VERSION 5.8 ;
BUSBITCHARS "[]" ;
DIVIDERCHAR "/" ;
UNITS
    DATABASE MICRONS 1000 ;
END UNITS

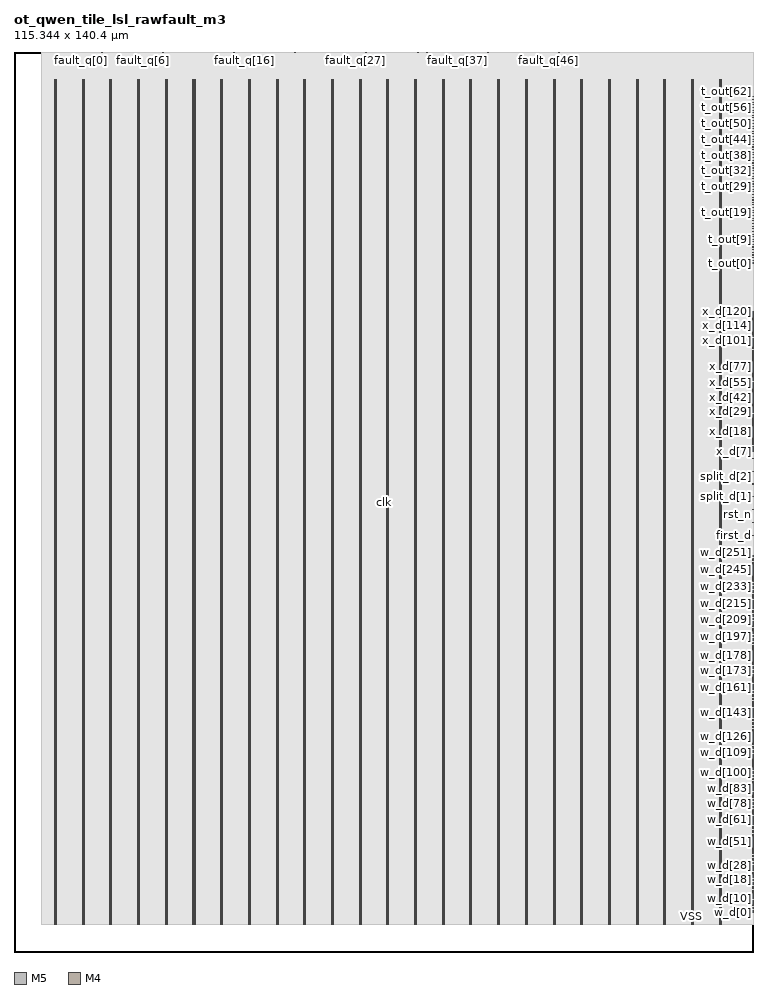
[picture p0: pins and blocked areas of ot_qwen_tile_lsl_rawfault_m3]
MACRO ot_qwen_tile_lsl_rawfault_m3
  FOREIGN ot_qwen_tile_lsl_rawfault_m3 0 0 ;
  CLASS BLOCK ;
  SIZE 115.344 BY 140.4 ;
  PIN clk
    DIRECTION INPUT ;
    USE SIGNAL ;
    PORT
      LAYER M5 ;
        RECT  57.636 69.96 57.684 70.44 ;
    END
  END clk
  PIN fault_q[0]
    DIRECTION OUTPUT ;
    USE SIGNAL ;
    PORT
      LAYER M5 ;
        RECT  10.368 140.316 10.392 140.4 ;
    END
  END fault_q[0]
  PIN fault_q[10]
    DIRECTION OUTPUT ;
    USE SIGNAL ;
    PORT
      LAYER M5 ;
        RECT  26.4 140.316 26.424 140.4 ;
    END
  END fault_q[10]
  PIN fault_q[11]
    DIRECTION OUTPUT ;
    USE SIGNAL ;
    PORT
      LAYER M5 ;
        RECT  27.792 140.316 27.816 140.4 ;
    END
  END fault_q[11]
  PIN fault_q[12]
    DIRECTION OUTPUT ;
    USE SIGNAL ;
    PORT
      LAYER M5 ;
        RECT  29.568 140.316 29.592 140.4 ;
    END
  END fault_q[12]
  PIN fault_q[13]
    DIRECTION OUTPUT ;
    USE SIGNAL ;
    PORT
      LAYER M5 ;
        RECT  31.152 140.316 31.176 140.4 ;
    END
  END fault_q[13]
  PIN fault_q[14]
    DIRECTION OUTPUT ;
    USE SIGNAL ;
    PORT
      LAYER M5 ;
        RECT  32.736 140.316 32.76 140.4 ;
    END
  END fault_q[14]
  PIN fault_q[15]
    DIRECTION OUTPUT ;
    USE SIGNAL ;
    PORT
      LAYER M5 ;
        RECT  34.32 140.316 34.344 140.4 ;
    END
  END fault_q[15]
  PIN fault_q[16]
    DIRECTION OUTPUT ;
    USE SIGNAL ;
    PORT
      LAYER M5 ;
        RECT  35.904 140.316 35.928 140.4 ;
    END
  END fault_q[16]
  PIN fault_q[17]
    DIRECTION OUTPUT ;
    USE SIGNAL ;
    PORT
      LAYER M5 ;
        RECT  37.488 140.316 37.512 140.4 ;
    END
  END fault_q[17]
  PIN fault_q[18]
    DIRECTION OUTPUT ;
    USE SIGNAL ;
    PORT
      LAYER M5 ;
        RECT  39.072 140.316 39.096 140.4 ;
    END
  END fault_q[18]
  PIN fault_q[19]
    DIRECTION OUTPUT ;
    USE SIGNAL ;
    PORT
      LAYER M5 ;
        RECT  40.656 140.316 40.68 140.4 ;
    END
  END fault_q[19]
  PIN fault_q[1]
    DIRECTION OUTPUT ;
    USE SIGNAL ;
    PORT
      LAYER M5 ;
        RECT  12.144 140.316 12.168 140.4 ;
    END
  END fault_q[1]
  PIN fault_q[20]
    DIRECTION OUTPUT ;
    USE SIGNAL ;
    PORT
      LAYER M5 ;
        RECT  42.24 140.316 42.264 140.4 ;
    END
  END fault_q[20]
  PIN fault_q[21]
    DIRECTION OUTPUT ;
    USE SIGNAL ;
    PORT
      LAYER M5 ;
        RECT  43.824 140.316 43.848 140.4 ;
    END
  END fault_q[21]
  PIN fault_q[22]
    DIRECTION OUTPUT ;
    USE SIGNAL ;
    PORT
      LAYER M5 ;
        RECT  45.024 140.316 45.048 140.4 ;
    END
  END fault_q[22]
  PIN fault_q[23]
    DIRECTION OUTPUT ;
    USE SIGNAL ;
    PORT
      LAYER M5 ;
        RECT  46.992 140.316 47.016 140.4 ;
    END
  END fault_q[23]
  PIN fault_q[24]
    DIRECTION OUTPUT ;
    USE SIGNAL ;
    PORT
      LAYER M5 ;
        RECT  48.576 140.316 48.6 140.4 ;
    END
  END fault_q[24]
  PIN fault_q[25]
    DIRECTION OUTPUT ;
    USE SIGNAL ;
    PORT
      LAYER M5 ;
        RECT  50.16 140.316 50.184 140.4 ;
    END
  END fault_q[25]
  PIN fault_q[26]
    DIRECTION OUTPUT ;
    USE SIGNAL ;
    PORT
      LAYER M5 ;
        RECT  51.744 140.316 51.768 140.4 ;
    END
  END fault_q[26]
  PIN fault_q[27]
    DIRECTION OUTPUT ;
    USE SIGNAL ;
    PORT
      LAYER M5 ;
        RECT  53.328 140.316 53.352 140.4 ;
    END
  END fault_q[27]
  PIN fault_q[28]
    DIRECTION OUTPUT ;
    USE SIGNAL ;
    PORT
      LAYER M5 ;
        RECT  54.912 140.316 54.936 140.4 ;
    END
  END fault_q[28]
  PIN fault_q[29]
    DIRECTION OUTPUT ;
    USE SIGNAL ;
    PORT
      LAYER M5 ;
        RECT  56.496 140.316 56.52 140.4 ;
    END
  END fault_q[29]
  PIN fault_q[2]
    DIRECTION OUTPUT ;
    USE SIGNAL ;
    PORT
      LAYER M5 ;
        RECT  13.728 140.316 13.752 140.4 ;
    END
  END fault_q[2]
  PIN fault_q[30]
    DIRECTION OUTPUT ;
    USE SIGNAL ;
    PORT
      LAYER M5 ;
        RECT  57.888 140.316 57.912 140.4 ;
    END
  END fault_q[30]
  PIN fault_q[31]
    DIRECTION OUTPUT ;
    USE SIGNAL ;
    PORT
      LAYER M5 ;
        RECT  59.664 140.316 59.688 140.4 ;
    END
  END fault_q[31]
  PIN fault_q[32]
    DIRECTION OUTPUT ;
    USE SIGNAL ;
    PORT
      LAYER M5 ;
        RECT  61.248 140.316 61.272 140.4 ;
    END
  END fault_q[32]
  PIN fault_q[33]
    DIRECTION OUTPUT ;
    USE SIGNAL ;
    PORT
      LAYER M5 ;
        RECT  63.024 140.316 63.048 140.4 ;
    END
  END fault_q[33]
  PIN fault_q[34]
    DIRECTION OUTPUT ;
    USE SIGNAL ;
    PORT
      LAYER M5 ;
        RECT  64.416 140.316 64.44 140.4 ;
    END
  END fault_q[34]
  PIN fault_q[35]
    DIRECTION OUTPUT ;
    USE SIGNAL ;
    PORT
      LAYER M5 ;
        RECT  66 140.316 66.024 140.4 ;
    END
  END fault_q[35]
  PIN fault_q[36]
    DIRECTION OUTPUT ;
    USE SIGNAL ;
    PORT
      LAYER M5 ;
        RECT  67.584 140.316 67.608 140.4 ;
    END
  END fault_q[36]
  PIN fault_q[37]
    DIRECTION OUTPUT ;
    USE SIGNAL ;
    PORT
      LAYER M5 ;
        RECT  69.168 140.316 69.192 140.4 ;
    END
  END fault_q[37]
  PIN fault_q[38]
    DIRECTION OUTPUT ;
    USE SIGNAL ;
    PORT
      LAYER M5 ;
        RECT  70.752 140.316 70.776 140.4 ;
    END
  END fault_q[38]
  PIN fault_q[39]
    DIRECTION OUTPUT ;
    USE SIGNAL ;
    PORT
      LAYER M5 ;
        RECT  72.336 140.316 72.36 140.4 ;
    END
  END fault_q[39]
  PIN fault_q[3]
    DIRECTION OUTPUT ;
    USE SIGNAL ;
    PORT
      LAYER M5 ;
        RECT  15.504 140.316 15.528 140.4 ;
    END
  END fault_q[3]
  PIN fault_q[40]
    DIRECTION OUTPUT ;
    USE SIGNAL ;
    PORT
      LAYER M5 ;
        RECT  73.92 140.316 73.944 140.4 ;
    END
  END fault_q[40]
  PIN fault_q[41]
    DIRECTION OUTPUT ;
    USE SIGNAL ;
    PORT
      LAYER M5 ;
        RECT  75.312 140.316 75.336 140.4 ;
    END
  END fault_q[41]
  PIN fault_q[42]
    DIRECTION OUTPUT ;
    USE SIGNAL ;
    PORT
      LAYER M5 ;
        RECT  77.088 140.316 77.112 140.4 ;
    END
  END fault_q[42]
  PIN fault_q[43]
    DIRECTION OUTPUT ;
    USE SIGNAL ;
    PORT
      LAYER M5 ;
        RECT  78.672 140.316 78.696 140.4 ;
    END
  END fault_q[43]
  PIN fault_q[44]
    DIRECTION OUTPUT ;
    USE SIGNAL ;
    PORT
      LAYER M5 ;
        RECT  80.256 140.316 80.28 140.4 ;
    END
  END fault_q[44]
  PIN fault_q[45]
    DIRECTION OUTPUT ;
    USE SIGNAL ;
    PORT
      LAYER M5 ;
        RECT  81.84 140.316 81.864 140.4 ;
    END
  END fault_q[45]
  PIN fault_q[46]
    DIRECTION OUTPUT ;
    USE SIGNAL ;
    PORT
      LAYER M5 ;
        RECT  83.424 140.316 83.448 140.4 ;
    END
  END fault_q[46]
  PIN fault_q[47]
    DIRECTION OUTPUT ;
    USE SIGNAL ;
    PORT
      LAYER M5 ;
        RECT  85.008 140.316 85.032 140.4 ;
    END
  END fault_q[47]
  PIN fault_q[48]
    DIRECTION OUTPUT ;
    USE SIGNAL ;
    PORT
      LAYER M5 ;
        RECT  86.592 140.316 86.616 140.4 ;
    END
  END fault_q[48]
  PIN fault_q[49]
    DIRECTION OUTPUT ;
    USE SIGNAL ;
    PORT
      LAYER M5 ;
        RECT  88.176 140.316 88.2 140.4 ;
    END
  END fault_q[49]
  PIN fault_q[4]
    DIRECTION OUTPUT ;
    USE SIGNAL ;
    PORT
      LAYER M5 ;
        RECT  16.896 140.316 16.92 140.4 ;
    END
  END fault_q[4]
  PIN fault_q[5]
    DIRECTION OUTPUT ;
    USE SIGNAL ;
    PORT
      LAYER M5 ;
        RECT  18.48 140.316 18.504 140.4 ;
    END
  END fault_q[5]
  PIN fault_q[6]
    DIRECTION OUTPUT ;
    USE SIGNAL ;
    PORT
      LAYER M5 ;
        RECT  20.064 140.316 20.088 140.4 ;
    END
  END fault_q[6]
  PIN fault_q[7]
    DIRECTION OUTPUT ;
    USE SIGNAL ;
    PORT
      LAYER M5 ;
        RECT  21.648 140.316 21.672 140.4 ;
    END
  END fault_q[7]
  PIN fault_q[8]
    DIRECTION OUTPUT ;
    USE SIGNAL ;
    PORT
      LAYER M5 ;
        RECT  23.232 140.316 23.256 140.4 ;
    END
  END fault_q[8]
  PIN fault_q[9]
    DIRECTION OUTPUT ;
    USE SIGNAL ;
    PORT
      LAYER M5 ;
        RECT  24.816 140.316 24.84 140.4 ;
    END
  END fault_q[9]
  PIN first_d
    DIRECTION INPUT ;
    USE SIGNAL ;
    PORT
      LAYER M4 ;
        RECT  115.26 64.992 115.344 65.016 ;
    END
  END first_d
  PIN rst_n
    DIRECTION INPUT ;
    USE SIGNAL ;
    PORT
      LAYER M4 ;
        RECT  115.26 67.008 115.344 67.032 ;
    END
  END rst_n
  PIN split_d[0]
    DIRECTION INPUT ;
    USE SIGNAL ;
    PORT
      LAYER M4 ;
        RECT  115.26 68.976 115.344 69 ;
    END
  END split_d[0]
  PIN split_d[1]
    DIRECTION INPUT ;
    USE SIGNAL ;
    PORT
      LAYER M4 ;
        RECT  115.26 70.992 115.344 71.016 ;
    END
  END split_d[1]
  PIN split_d[2]
    DIRECTION INPUT ;
    USE SIGNAL ;
    PORT
      LAYER M4 ;
        RECT  115.26 73.008 115.344 73.032 ;
    END
  END split_d[2]
  PIN split_d[3]
    DIRECTION INPUT ;
    USE SIGNAL ;
    PORT
      LAYER M4 ;
        RECT  115.26 74.976 115.344 75 ;
    END
  END split_d[3]
  PIN t_out[0]
    DIRECTION OUTPUT ;
    USE SIGNAL ;
    PORT
      LAYER M4 ;
        RECT  115.26 107.472 115.344 107.496 ;
    END
  END t_out[0]
  PIN t_out[10]
    DIRECTION OUTPUT ;
    USE SIGNAL ;
    PORT
      LAYER M4 ;
        RECT  115.26 111.6 115.344 111.624 ;
    END
  END t_out[10]
  PIN t_out[11]
    DIRECTION OUTPUT ;
    USE SIGNAL ;
    PORT
      LAYER M4 ;
        RECT  115.26 111.984 115.344 112.008 ;
    END
  END t_out[11]
  PIN t_out[12]
    DIRECTION OUTPUT ;
    USE SIGNAL ;
    PORT
      LAYER M4 ;
        RECT  115.26 112.416 115.344 112.44 ;
    END
  END t_out[12]
  PIN t_out[13]
    DIRECTION OUTPUT ;
    USE SIGNAL ;
    PORT
      LAYER M4 ;
        RECT  115.26 112.848 115.344 112.872 ;
    END
  END t_out[13]
  PIN t_out[14]
    DIRECTION OUTPUT ;
    USE SIGNAL ;
    PORT
      LAYER M4 ;
        RECT  115.26 113.232 115.344 113.256 ;
    END
  END t_out[14]
  PIN t_out[15]
    DIRECTION OUTPUT ;
    USE SIGNAL ;
    PORT
      LAYER M4 ;
        RECT  115.26 113.664 115.344 113.688 ;
    END
  END t_out[15]
  PIN t_out[16]
    DIRECTION OUTPUT ;
    USE SIGNAL ;
    PORT
      LAYER M4 ;
        RECT  115.26 114.048 115.344 114.072 ;
    END
  END t_out[16]
  PIN t_out[17]
    DIRECTION OUTPUT ;
    USE SIGNAL ;
    PORT
      LAYER M4 ;
        RECT  115.26 114.48 115.344 114.504 ;
    END
  END t_out[17]
  PIN t_out[18]
    DIRECTION OUTPUT ;
    USE SIGNAL ;
    PORT
      LAYER M4 ;
        RECT  115.26 114.864 115.344 114.888 ;
    END
  END t_out[18]
  PIN t_out[19]
    DIRECTION OUTPUT ;
    USE SIGNAL ;
    PORT
      LAYER M4 ;
        RECT  115.26 115.296 115.344 115.32 ;
    END
  END t_out[19]
  PIN t_out[1]
    DIRECTION OUTPUT ;
    USE SIGNAL ;
    PORT
      LAYER M4 ;
        RECT  115.26 107.904 115.344 107.928 ;
    END
  END t_out[1]
  PIN t_out[20]
    DIRECTION OUTPUT ;
    USE SIGNAL ;
    PORT
      LAYER M4 ;
        RECT  115.26 115.68 115.344 115.704 ;
    END
  END t_out[20]
  PIN t_out[21]
    DIRECTION OUTPUT ;
    USE SIGNAL ;
    PORT
      LAYER M4 ;
        RECT  115.26 116.112 115.344 116.136 ;
    END
  END t_out[21]
  PIN t_out[22]
    DIRECTION OUTPUT ;
    USE SIGNAL ;
    PORT
      LAYER M4 ;
        RECT  115.26 116.544 115.344 116.568 ;
    END
  END t_out[22]
  PIN t_out[23]
    DIRECTION OUTPUT ;
    USE SIGNAL ;
    PORT
      LAYER M4 ;
        RECT  115.26 116.928 115.344 116.952 ;
    END
  END t_out[23]
  PIN t_out[24]
    DIRECTION OUTPUT ;
    USE SIGNAL ;
    PORT
      LAYER M4 ;
        RECT  115.26 117.312 115.344 117.336 ;
    END
  END t_out[24]
  PIN t_out[25]
    DIRECTION OUTPUT ;
    USE SIGNAL ;
    PORT
      LAYER M4 ;
        RECT  115.26 117.744 115.344 117.768 ;
    END
  END t_out[25]
  PIN t_out[26]
    DIRECTION OUTPUT ;
    USE SIGNAL ;
    PORT
      LAYER M4 ;
        RECT  115.26 118.128 115.344 118.152 ;
    END
  END t_out[26]
  PIN t_out[27]
    DIRECTION OUTPUT ;
    USE SIGNAL ;
    PORT
      LAYER M4 ;
        RECT  115.26 118.608 115.344 118.632 ;
    END
  END t_out[27]
  PIN t_out[28]
    DIRECTION OUTPUT ;
    USE SIGNAL ;
    PORT
      LAYER M4 ;
        RECT  115.26 118.992 115.344 119.016 ;
    END
  END t_out[28]
  PIN t_out[29]
    DIRECTION OUTPUT ;
    USE SIGNAL ;
    PORT
      LAYER M4 ;
        RECT  115.26 119.424 115.344 119.448 ;
    END
  END t_out[29]
  PIN t_out[2]
    DIRECTION OUTPUT ;
    USE SIGNAL ;
    PORT
      LAYER M4 ;
        RECT  115.26 108.288 115.344 108.312 ;
    END
  END t_out[2]
  PIN t_out[30]
    DIRECTION OUTPUT ;
    USE SIGNAL ;
    PORT
      LAYER M4 ;
        RECT  115.26 119.808 115.344 119.832 ;
    END
  END t_out[30]
  PIN t_out[31]
    DIRECTION OUTPUT ;
    USE SIGNAL ;
    PORT
      LAYER M4 ;
        RECT  115.26 120.192 115.344 120.216 ;
    END
  END t_out[31]
  PIN t_out[32]
    DIRECTION OUTPUT ;
    USE SIGNAL ;
    PORT
      LAYER M4 ;
        RECT  115.26 120.624 115.344 120.648 ;
    END
  END t_out[32]
  PIN t_out[33]
    DIRECTION OUTPUT ;
    USE SIGNAL ;
    PORT
      LAYER M4 ;
        RECT  115.26 121.008 115.344 121.032 ;
    END
  END t_out[33]
  PIN t_out[34]
    DIRECTION OUTPUT ;
    USE SIGNAL ;
    PORT
      LAYER M4 ;
        RECT  115.26 121.488 115.344 121.512 ;
    END
  END t_out[34]
  PIN t_out[35]
    DIRECTION OUTPUT ;
    USE SIGNAL ;
    PORT
      LAYER M4 ;
        RECT  115.26 121.872 115.344 121.896 ;
    END
  END t_out[35]
  PIN t_out[36]
    DIRECTION OUTPUT ;
    USE SIGNAL ;
    PORT
      LAYER M4 ;
        RECT  115.26 122.304 115.344 122.328 ;
    END
  END t_out[36]
  PIN t_out[37]
    DIRECTION OUTPUT ;
    USE SIGNAL ;
    PORT
      LAYER M4 ;
        RECT  115.26 122.688 115.344 122.712 ;
    END
  END t_out[37]
  PIN t_out[38]
    DIRECTION OUTPUT ;
    USE SIGNAL ;
    PORT
      LAYER M4 ;
        RECT  115.26 123.072 115.344 123.096 ;
    END
  END t_out[38]
  PIN t_out[39]
    DIRECTION OUTPUT ;
    USE SIGNAL ;
    PORT
      LAYER M4 ;
        RECT  115.26 123.504 115.344 123.528 ;
    END
  END t_out[39]
  PIN t_out[3]
    DIRECTION OUTPUT ;
    USE SIGNAL ;
    PORT
      LAYER M4 ;
        RECT  115.26 108.72 115.344 108.744 ;
    END
  END t_out[3]
  PIN t_out[40]
    DIRECTION OUTPUT ;
    USE SIGNAL ;
    PORT
      LAYER M4 ;
        RECT  115.26 123.888 115.344 123.912 ;
    END
  END t_out[40]
  PIN t_out[41]
    DIRECTION OUTPUT ;
    USE SIGNAL ;
    PORT
      LAYER M4 ;
        RECT  115.26 124.368 115.344 124.392 ;
    END
  END t_out[41]
  PIN t_out[42]
    DIRECTION OUTPUT ;
    USE SIGNAL ;
    PORT
      LAYER M4 ;
        RECT  115.26 124.752 115.344 124.776 ;
    END
  END t_out[42]
  PIN t_out[43]
    DIRECTION OUTPUT ;
    USE SIGNAL ;
    PORT
      LAYER M4 ;
        RECT  115.26 125.136 115.344 125.16 ;
    END
  END t_out[43]
  PIN t_out[44]
    DIRECTION OUTPUT ;
    USE SIGNAL ;
    PORT
      LAYER M4 ;
        RECT  115.26 125.568 115.344 125.592 ;
    END
  END t_out[44]
  PIN t_out[45]
    DIRECTION OUTPUT ;
    USE SIGNAL ;
    PORT
      LAYER M4 ;
        RECT  115.26 125.952 115.344 125.976 ;
    END
  END t_out[45]
  PIN t_out[46]
    DIRECTION OUTPUT ;
    USE SIGNAL ;
    PORT
      LAYER M4 ;
        RECT  115.26 126.384 115.344 126.408 ;
    END
  END t_out[46]
  PIN t_out[47]
    DIRECTION OUTPUT ;
    USE SIGNAL ;
    PORT
      LAYER M4 ;
        RECT  115.26 126.768 115.344 126.792 ;
    END
  END t_out[47]
  PIN t_out[48]
    DIRECTION OUTPUT ;
    USE SIGNAL ;
    PORT
      LAYER M4 ;
        RECT  115.26 127.248 115.344 127.272 ;
    END
  END t_out[48]
  PIN t_out[49]
    DIRECTION OUTPUT ;
    USE SIGNAL ;
    PORT
      LAYER M4 ;
        RECT  115.26 127.632 115.344 127.656 ;
    END
  END t_out[49]
  PIN t_out[4]
    DIRECTION OUTPUT ;
    USE SIGNAL ;
    PORT
      LAYER M4 ;
        RECT  115.26 109.104 115.344 109.128 ;
    END
  END t_out[4]
  PIN t_out[50]
    DIRECTION OUTPUT ;
    USE SIGNAL ;
    PORT
      LAYER M4 ;
        RECT  115.26 128.016 115.344 128.04 ;
    END
  END t_out[50]
  PIN t_out[51]
    DIRECTION OUTPUT ;
    USE SIGNAL ;
    PORT
      LAYER M4 ;
        RECT  115.26 128.448 115.344 128.472 ;
    END
  END t_out[51]
  PIN t_out[52]
    DIRECTION OUTPUT ;
    USE SIGNAL ;
    PORT
      LAYER M4 ;
        RECT  115.26 128.832 115.344 128.856 ;
    END
  END t_out[52]
  PIN t_out[53]
    DIRECTION OUTPUT ;
    USE SIGNAL ;
    PORT
      LAYER M4 ;
        RECT  115.26 129.264 115.344 129.288 ;
    END
  END t_out[53]
  PIN t_out[54]
    DIRECTION OUTPUT ;
    USE SIGNAL ;
    PORT
      LAYER M4 ;
        RECT  115.26 129.648 115.344 129.672 ;
    END
  END t_out[54]
  PIN t_out[55]
    DIRECTION OUTPUT ;
    USE SIGNAL ;
    PORT
      LAYER M4 ;
        RECT  115.26 130.128 115.344 130.152 ;
    END
  END t_out[55]
  PIN t_out[56]
    DIRECTION OUTPUT ;
    USE SIGNAL ;
    PORT
      LAYER M4 ;
        RECT  115.26 130.512 115.344 130.536 ;
    END
  END t_out[56]
  PIN t_out[57]
    DIRECTION OUTPUT ;
    USE SIGNAL ;
    PORT
      LAYER M4 ;
        RECT  115.26 130.896 115.344 130.92 ;
    END
  END t_out[57]
  PIN t_out[58]
    DIRECTION OUTPUT ;
    USE SIGNAL ;
    PORT
      LAYER M4 ;
        RECT  115.26 131.328 115.344 131.352 ;
    END
  END t_out[58]
  PIN t_out[59]
    DIRECTION OUTPUT ;
    USE SIGNAL ;
    PORT
      LAYER M4 ;
        RECT  115.26 131.712 115.344 131.736 ;
    END
  END t_out[59]
  PIN t_out[5]
    DIRECTION OUTPUT ;
    USE SIGNAL ;
    PORT
      LAYER M4 ;
        RECT  115.26 109.536 115.344 109.56 ;
    END
  END t_out[5]
  PIN t_out[60]
    DIRECTION OUTPUT ;
    USE SIGNAL ;
    PORT
      LAYER M4 ;
        RECT  115.26 132.144 115.344 132.168 ;
    END
  END t_out[60]
  PIN t_out[61]
    DIRECTION OUTPUT ;
    USE SIGNAL ;
    PORT
      LAYER M4 ;
        RECT  115.26 132.528 115.344 132.552 ;
    END
  END t_out[61]
  PIN t_out[62]
    DIRECTION OUTPUT ;
    USE SIGNAL ;
    PORT
      LAYER M4 ;
        RECT  115.26 132.96 115.344 132.984 ;
    END
  END t_out[62]
  PIN t_out[63]
    DIRECTION OUTPUT ;
    USE SIGNAL ;
    PORT
      LAYER M4 ;
        RECT  115.26 133.392 115.344 133.416 ;
    END
  END t_out[63]
  PIN t_out[6]
    DIRECTION OUTPUT ;
    USE SIGNAL ;
    PORT
      LAYER M4 ;
        RECT  115.26 109.968 115.344 109.992 ;
    END
  END t_out[6]
  PIN t_out[7]
    DIRECTION OUTPUT ;
    USE SIGNAL ;
    PORT
      LAYER M4 ;
        RECT  115.26 110.352 115.344 110.376 ;
    END
  END t_out[7]
  PIN t_out[8]
    DIRECTION OUTPUT ;
    USE SIGNAL ;
    PORT
      LAYER M4 ;
        RECT  115.26 110.784 115.344 110.808 ;
    END
  END t_out[8]
  PIN t_out[9]
    DIRECTION OUTPUT ;
    USE SIGNAL ;
    PORT
      LAYER M4 ;
        RECT  115.26 111.168 115.344 111.192 ;
    END
  END t_out[9]
  PIN v_d
    DIRECTION INPUT ;
    USE SIGNAL ;
    PORT
      LAYER M4 ;
        RECT  115.26 76.992 115.344 77.016 ;
    END
  END v_d
  PIN w_d[0]
    DIRECTION INPUT ;
    USE SIGNAL ;
    PORT
      LAYER M4 ;
        RECT  115.26 6.096 115.344 6.12 ;
    END
  END w_d[0]
  PIN w_d[100]
    DIRECTION INPUT ;
    USE SIGNAL ;
    PORT
      LAYER M4 ;
        RECT  115.26 27.984 115.344 28.008 ;
    END
  END w_d[100]
  PIN w_d[101]
    DIRECTION INPUT ;
    USE SIGNAL ;
    PORT
      LAYER M4 ;
        RECT  115.26 28.176 115.344 28.2 ;
    END
  END w_d[101]
  PIN w_d[102]
    DIRECTION INPUT ;
    USE SIGNAL ;
    PORT
      LAYER M4 ;
        RECT  115.26 28.416 115.344 28.44 ;
    END
  END w_d[102]
  PIN w_d[103]
    DIRECTION INPUT ;
    USE SIGNAL ;
    PORT
      LAYER M4 ;
        RECT  115.26 28.608 115.344 28.632 ;
    END
  END w_d[103]
  PIN w_d[104]
    DIRECTION INPUT ;
    USE SIGNAL ;
    PORT
      LAYER M4 ;
        RECT  115.26 28.848 115.344 28.872 ;
    END
  END w_d[104]
  PIN w_d[105]
    DIRECTION INPUT ;
    USE SIGNAL ;
    PORT
      LAYER M4 ;
        RECT  115.26 29.04 115.344 29.064 ;
    END
  END w_d[105]
  PIN w_d[106]
    DIRECTION INPUT ;
    USE SIGNAL ;
    PORT
      LAYER M4 ;
        RECT  115.26 29.328 115.344 29.352 ;
    END
  END w_d[106]
  PIN w_d[107]
    DIRECTION INPUT ;
    USE SIGNAL ;
    PORT
      LAYER M4 ;
        RECT  115.26 29.52 115.344 29.544 ;
    END
  END w_d[107]
  PIN w_d[108]
    DIRECTION INPUT ;
    USE SIGNAL ;
    PORT
      LAYER M4 ;
        RECT  115.26 29.712 115.344 29.736 ;
    END
  END w_d[108]
  PIN w_d[109]
    DIRECTION INPUT ;
    USE SIGNAL ;
    PORT
      LAYER M4 ;
        RECT  115.26 29.952 115.344 29.976 ;
    END
  END w_d[109]
  PIN w_d[10]
    DIRECTION INPUT ;
    USE SIGNAL ;
    PORT
      LAYER M4 ;
        RECT  115.26 8.304 115.344 8.328 ;
    END
  END w_d[10]
  PIN w_d[110]
    DIRECTION INPUT ;
    USE SIGNAL ;
    PORT
      LAYER M4 ;
        RECT  115.26 30.144 115.344 30.168 ;
    END
  END w_d[110]
  PIN w_d[111]
    DIRECTION INPUT ;
    USE SIGNAL ;
    PORT
      LAYER M4 ;
        RECT  115.26 30.384 115.344 30.408 ;
    END
  END w_d[111]
  PIN w_d[112]
    DIRECTION INPUT ;
    USE SIGNAL ;
    PORT
      LAYER M4 ;
        RECT  115.26 30.576 115.344 30.6 ;
    END
  END w_d[112]
  PIN w_d[113]
    DIRECTION INPUT ;
    USE SIGNAL ;
    PORT
      LAYER M4 ;
        RECT  115.26 30.768 115.344 30.792 ;
    END
  END w_d[113]
  PIN w_d[114]
    DIRECTION INPUT ;
    USE SIGNAL ;
    PORT
      LAYER M4 ;
        RECT  115.26 31.056 115.344 31.08 ;
    END
  END w_d[114]
  PIN w_d[115]
    DIRECTION INPUT ;
    USE SIGNAL ;
    PORT
      LAYER M4 ;
        RECT  115.26 31.248 115.344 31.272 ;
    END
  END w_d[115]
  PIN w_d[116]
    DIRECTION INPUT ;
    USE SIGNAL ;
    PORT
      LAYER M4 ;
        RECT  115.26 31.488 115.344 31.512 ;
    END
  END w_d[116]
  PIN w_d[117]
    DIRECTION INPUT ;
    USE SIGNAL ;
    PORT
      LAYER M4 ;
        RECT  115.26 31.68 115.344 31.704 ;
    END
  END w_d[117]
  PIN w_d[118]
    DIRECTION INPUT ;
    USE SIGNAL ;
    PORT
      LAYER M4 ;
        RECT  115.26 31.92 115.344 31.944 ;
    END
  END w_d[118]
  PIN w_d[119]
    DIRECTION INPUT ;
    USE SIGNAL ;
    PORT
      LAYER M4 ;
        RECT  115.26 32.112 115.344 32.136 ;
    END
  END w_d[119]
  PIN w_d[11]
    DIRECTION INPUT ;
    USE SIGNAL ;
    PORT
      LAYER M4 ;
        RECT  115.26 8.496 115.344 8.52 ;
    END
  END w_d[11]
  PIN w_d[120]
    DIRECTION INPUT ;
    USE SIGNAL ;
    PORT
      LAYER M4 ;
        RECT  115.26 32.304 115.344 32.328 ;
    END
  END w_d[120]
  PIN w_d[121]
    DIRECTION INPUT ;
    USE SIGNAL ;
    PORT
      LAYER M4 ;
        RECT  115.26 32.592 115.344 32.616 ;
    END
  END w_d[121]
  PIN w_d[122]
    DIRECTION INPUT ;
    USE SIGNAL ;
    PORT
      LAYER M4 ;
        RECT  115.26 32.784 115.344 32.808 ;
    END
  END w_d[122]
  PIN w_d[123]
    DIRECTION INPUT ;
    USE SIGNAL ;
    PORT
      LAYER M4 ;
        RECT  115.26 33.024 115.344 33.048 ;
    END
  END w_d[123]
  PIN w_d[124]
    DIRECTION INPUT ;
    USE SIGNAL ;
    PORT
      LAYER M4 ;
        RECT  115.26 33.216 115.344 33.24 ;
    END
  END w_d[124]
  PIN w_d[125]
    DIRECTION INPUT ;
    USE SIGNAL ;
    PORT
      LAYER M4 ;
        RECT  115.26 33.408 115.344 33.432 ;
    END
  END w_d[125]
  PIN w_d[126]
    DIRECTION INPUT ;
    USE SIGNAL ;
    PORT
      LAYER M4 ;
        RECT  115.26 33.648 115.344 33.672 ;
    END
  END w_d[126]
  PIN w_d[127]
    DIRECTION INPUT ;
    USE SIGNAL ;
    PORT
      LAYER M4 ;
        RECT  115.26 33.84 115.344 33.864 ;
    END
  END w_d[127]
  PIN w_d[128]
    DIRECTION INPUT ;
    USE SIGNAL ;
    PORT
      LAYER M4 ;
        RECT  115.26 34.08 115.344 34.104 ;
    END
  END w_d[128]
  PIN w_d[129]
    DIRECTION INPUT ;
    USE SIGNAL ;
    PORT
      LAYER M4 ;
        RECT  115.26 34.32 115.344 34.344 ;
    END
  END w_d[129]
  PIN w_d[12]
    DIRECTION INPUT ;
    USE SIGNAL ;
    PORT
      LAYER M4 ;
        RECT  115.26 8.736 115.344 8.76 ;
    END
  END w_d[12]
  PIN w_d[130]
    DIRECTION INPUT ;
    USE SIGNAL ;
    PORT
      LAYER M4 ;
        RECT  115.26 34.512 115.344 34.536 ;
    END
  END w_d[130]
  PIN w_d[131]
    DIRECTION INPUT ;
    USE SIGNAL ;
    PORT
      LAYER M4 ;
        RECT  115.26 34.752 115.344 34.776 ;
    END
  END w_d[131]
  PIN w_d[132]
    DIRECTION INPUT ;
    USE SIGNAL ;
    PORT
      LAYER M4 ;
        RECT  115.26 34.992 115.344 35.016 ;
    END
  END w_d[132]
  PIN w_d[133]
    DIRECTION INPUT ;
    USE SIGNAL ;
    PORT
      LAYER M4 ;
        RECT  115.26 35.184 115.344 35.208 ;
    END
  END w_d[133]
  PIN w_d[134]
    DIRECTION INPUT ;
    USE SIGNAL ;
    PORT
      LAYER M4 ;
        RECT  115.26 35.424 115.344 35.448 ;
    END
  END w_d[134]
  PIN w_d[135]
    DIRECTION INPUT ;
    USE SIGNAL ;
    PORT
      LAYER M4 ;
        RECT  115.26 35.616 115.344 35.64 ;
    END
  END w_d[135]
  PIN w_d[136]
    DIRECTION INPUT ;
    USE SIGNAL ;
    PORT
      LAYER M4 ;
        RECT  115.26 35.856 115.344 35.88 ;
    END
  END w_d[136]
  PIN w_d[137]
    DIRECTION INPUT ;
    USE SIGNAL ;
    PORT
      LAYER M4 ;
        RECT  115.26 36.048 115.344 36.072 ;
    END
  END w_d[137]
  PIN w_d[138]
    DIRECTION INPUT ;
    USE SIGNAL ;
    PORT
      LAYER M4 ;
        RECT  115.26 36.288 115.344 36.312 ;
    END
  END w_d[138]
  PIN w_d[139]
    DIRECTION INPUT ;
    USE SIGNAL ;
    PORT
      LAYER M4 ;
        RECT  115.26 36.528 115.344 36.552 ;
    END
  END w_d[139]
  PIN w_d[13]
    DIRECTION INPUT ;
    USE SIGNAL ;
    PORT
      LAYER M4 ;
        RECT  115.26 8.928 115.344 8.952 ;
    END
  END w_d[13]
  PIN w_d[140]
    DIRECTION INPUT ;
    USE SIGNAL ;
    PORT
      LAYER M4 ;
        RECT  115.26 36.72 115.344 36.744 ;
    END
  END w_d[140]
  PIN w_d[141]
    DIRECTION INPUT ;
    USE SIGNAL ;
    PORT
      LAYER M4 ;
        RECT  115.26 36.96 115.344 36.984 ;
    END
  END w_d[141]
  PIN w_d[142]
    DIRECTION INPUT ;
    USE SIGNAL ;
    PORT
      LAYER M4 ;
        RECT  115.26 37.152 115.344 37.176 ;
    END
  END w_d[142]
  PIN w_d[143]
    DIRECTION INPUT ;
    USE SIGNAL ;
    PORT
      LAYER M4 ;
        RECT  115.26 37.392 115.344 37.416 ;
    END
  END w_d[143]
  PIN w_d[144]
    DIRECTION INPUT ;
    USE SIGNAL ;
    PORT
      LAYER M4 ;
        RECT  115.26 37.584 115.344 37.608 ;
    END
  END w_d[144]
  PIN w_d[145]
    DIRECTION INPUT ;
    USE SIGNAL ;
    PORT
      LAYER M4 ;
        RECT  115.26 37.824 115.344 37.848 ;
    END
  END w_d[145]
  PIN w_d[146]
    DIRECTION INPUT ;
    USE SIGNAL ;
    PORT
      LAYER M4 ;
        RECT  115.26 38.016 115.344 38.04 ;
    END
  END w_d[146]
  PIN w_d[147]
    DIRECTION INPUT ;
    USE SIGNAL ;
    PORT
      LAYER M4 ;
        RECT  115.26 38.256 115.344 38.28 ;
    END
  END w_d[147]
  PIN w_d[148]
    DIRECTION INPUT ;
    USE SIGNAL ;
    PORT
      LAYER M4 ;
        RECT  115.26 38.496 115.344 38.52 ;
    END
  END w_d[148]
  PIN w_d[149]
    DIRECTION INPUT ;
    USE SIGNAL ;
    PORT
      LAYER M4 ;
        RECT  115.26 38.688 115.344 38.712 ;
    END
  END w_d[149]
  PIN w_d[14]
    DIRECTION INPUT ;
    USE SIGNAL ;
    PORT
      LAYER M4 ;
        RECT  115.26 9.168 115.344 9.192 ;
    END
  END w_d[14]
  PIN w_d[150]
    DIRECTION INPUT ;
    USE SIGNAL ;
    PORT
      LAYER M4 ;
        RECT  115.26 38.928 115.344 38.952 ;
    END
  END w_d[150]
  PIN w_d[151]
    DIRECTION INPUT ;
    USE SIGNAL ;
    PORT
      LAYER M4 ;
        RECT  115.26 39.12 115.344 39.144 ;
    END
  END w_d[151]
  PIN w_d[152]
    DIRECTION INPUT ;
    USE SIGNAL ;
    PORT
      LAYER M4 ;
        RECT  115.26 39.36 115.344 39.384 ;
    END
  END w_d[152]
  PIN w_d[153]
    DIRECTION INPUT ;
    USE SIGNAL ;
    PORT
      LAYER M4 ;
        RECT  115.26 39.552 115.344 39.576 ;
    END
  END w_d[153]
  PIN w_d[154]
    DIRECTION INPUT ;
    USE SIGNAL ;
    PORT
      LAYER M4 ;
        RECT  115.26 39.792 115.344 39.816 ;
    END
  END w_d[154]
  PIN w_d[155]
    DIRECTION INPUT ;
    USE SIGNAL ;
    PORT
      LAYER M4 ;
        RECT  115.26 39.984 115.344 40.008 ;
    END
  END w_d[155]
  PIN w_d[156]
    DIRECTION INPUT ;
    USE SIGNAL ;
    PORT
      LAYER M4 ;
        RECT  115.26 40.224 115.344 40.248 ;
    END
  END w_d[156]
  PIN w_d[157]
    DIRECTION INPUT ;
    USE SIGNAL ;
    PORT
      LAYER M4 ;
        RECT  115.26 40.464 115.344 40.488 ;
    END
  END w_d[157]
  PIN w_d[158]
    DIRECTION INPUT ;
    USE SIGNAL ;
    PORT
      LAYER M4 ;
        RECT  115.26 40.656 115.344 40.68 ;
    END
  END w_d[158]
  PIN w_d[159]
    DIRECTION INPUT ;
    USE SIGNAL ;
    PORT
      LAYER M4 ;
        RECT  115.26 40.896 115.344 40.92 ;
    END
  END w_d[159]
  PIN w_d[15]
    DIRECTION INPUT ;
    USE SIGNAL ;
    PORT
      LAYER M4 ;
        RECT  115.26 9.36 115.344 9.384 ;
    END
  END w_d[15]
  PIN w_d[160]
    DIRECTION INPUT ;
    USE SIGNAL ;
    PORT
      LAYER M4 ;
        RECT  115.26 41.088 115.344 41.112 ;
    END
  END w_d[160]
  PIN w_d[161]
    DIRECTION INPUT ;
    USE SIGNAL ;
    PORT
      LAYER M4 ;
        RECT  115.26 41.328 115.344 41.352 ;
    END
  END w_d[161]
  PIN w_d[162]
    DIRECTION INPUT ;
    USE SIGNAL ;
    PORT
      LAYER M4 ;
        RECT  115.26 41.52 115.344 41.544 ;
    END
  END w_d[162]
  PIN w_d[163]
    DIRECTION INPUT ;
    USE SIGNAL ;
    PORT
      LAYER M4 ;
        RECT  115.26 41.712 115.344 41.736 ;
    END
  END w_d[163]
  PIN w_d[164]
    DIRECTION INPUT ;
    USE SIGNAL ;
    PORT
      LAYER M4 ;
        RECT  115.26 42 115.344 42.024 ;
    END
  END w_d[164]
  PIN w_d[165]
    DIRECTION INPUT ;
    USE SIGNAL ;
    PORT
      LAYER M4 ;
        RECT  115.26 42.192 115.344 42.216 ;
    END
  END w_d[165]
  PIN w_d[166]
    DIRECTION INPUT ;
    USE SIGNAL ;
    PORT
      LAYER M4 ;
        RECT  115.26 42.432 115.344 42.456 ;
    END
  END w_d[166]
  PIN w_d[167]
    DIRECTION INPUT ;
    USE SIGNAL ;
    PORT
      LAYER M4 ;
        RECT  115.26 42.624 115.344 42.648 ;
    END
  END w_d[167]
  PIN w_d[168]
    DIRECTION INPUT ;
    USE SIGNAL ;
    PORT
      LAYER M4 ;
        RECT  115.26 42.816 115.344 42.84 ;
    END
  END w_d[168]
  PIN w_d[169]
    DIRECTION INPUT ;
    USE SIGNAL ;
    PORT
      LAYER M4 ;
        RECT  115.26 43.056 115.344 43.08 ;
    END
  END w_d[169]
  PIN w_d[16]
    DIRECTION INPUT ;
    USE SIGNAL ;
    PORT
      LAYER M4 ;
        RECT  115.26 9.6 115.344 9.624 ;
    END
  END w_d[16]
  PIN w_d[170]
    DIRECTION INPUT ;
    USE SIGNAL ;
    PORT
      LAYER M4 ;
        RECT  115.26 43.248 115.344 43.272 ;
    END
  END w_d[170]
  PIN w_d[171]
    DIRECTION INPUT ;
    USE SIGNAL ;
    PORT
      LAYER M4 ;
        RECT  115.26 43.536 115.344 43.56 ;
    END
  END w_d[171]
  PIN w_d[172]
    DIRECTION INPUT ;
    USE SIGNAL ;
    PORT
      LAYER M4 ;
        RECT  115.26 43.728 115.344 43.752 ;
    END
  END w_d[172]
  PIN w_d[173]
    DIRECTION INPUT ;
    USE SIGNAL ;
    PORT
      LAYER M4 ;
        RECT  115.26 43.968 115.344 43.992 ;
    END
  END w_d[173]
  PIN w_d[174]
    DIRECTION INPUT ;
    USE SIGNAL ;
    PORT
      LAYER M4 ;
        RECT  115.26 44.16 115.344 44.184 ;
    END
  END w_d[174]
  PIN w_d[175]
    DIRECTION INPUT ;
    USE SIGNAL ;
    PORT
      LAYER M4 ;
        RECT  115.26 44.352 115.344 44.376 ;
    END
  END w_d[175]
  PIN w_d[176]
    DIRECTION INPUT ;
    USE SIGNAL ;
    PORT
      LAYER M4 ;
        RECT  115.26 44.592 115.344 44.616 ;
    END
  END w_d[176]
  PIN w_d[177]
    DIRECTION INPUT ;
    USE SIGNAL ;
    PORT
      LAYER M4 ;
        RECT  115.26 44.784 115.344 44.808 ;
    END
  END w_d[177]
  PIN w_d[178]
    DIRECTION INPUT ;
    USE SIGNAL ;
    PORT
      LAYER M4 ;
        RECT  115.26 45.072 115.344 45.096 ;
    END
  END w_d[178]
  PIN w_d[179]
    DIRECTION INPUT ;
    USE SIGNAL ;
    PORT
      LAYER M4 ;
        RECT  115.26 45.264 115.344 45.288 ;
    END
  END w_d[179]
  PIN w_d[17]
    DIRECTION INPUT ;
    USE SIGNAL ;
    PORT
      LAYER M4 ;
        RECT  115.26 9.84 115.344 9.864 ;
    END
  END w_d[17]
  PIN w_d[180]
    DIRECTION INPUT ;
    USE SIGNAL ;
    PORT
      LAYER M4 ;
        RECT  115.26 45.456 115.344 45.48 ;
    END
  END w_d[180]
  PIN w_d[181]
    DIRECTION INPUT ;
    USE SIGNAL ;
    PORT
      LAYER M4 ;
        RECT  115.26 45.696 115.344 45.72 ;
    END
  END w_d[181]
  PIN w_d[182]
    DIRECTION INPUT ;
    USE SIGNAL ;
    PORT
      LAYER M4 ;
        RECT  115.26 45.888 115.344 45.912 ;
    END
  END w_d[182]
  PIN w_d[183]
    DIRECTION INPUT ;
    USE SIGNAL ;
    PORT
      LAYER M4 ;
        RECT  115.26 46.128 115.344 46.152 ;
    END
  END w_d[183]
  PIN w_d[184]
    DIRECTION INPUT ;
    USE SIGNAL ;
    PORT
      LAYER M4 ;
        RECT  115.26 46.32 115.344 46.344 ;
    END
  END w_d[184]
  PIN w_d[185]
    DIRECTION INPUT ;
    USE SIGNAL ;
    PORT
      LAYER M4 ;
        RECT  115.26 46.608 115.344 46.632 ;
    END
  END w_d[185]
  PIN w_d[186]
    DIRECTION INPUT ;
    USE SIGNAL ;
    PORT
      LAYER M4 ;
        RECT  115.26 46.8 115.344 46.824 ;
    END
  END w_d[186]
  PIN w_d[187]
    DIRECTION INPUT ;
    USE SIGNAL ;
    PORT
      LAYER M4 ;
        RECT  115.26 46.992 115.344 47.016 ;
    END
  END w_d[187]
  PIN w_d[188]
    DIRECTION INPUT ;
    USE SIGNAL ;
    PORT
      LAYER M4 ;
        RECT  115.26 47.232 115.344 47.256 ;
    END
  END w_d[188]
  PIN w_d[189]
    DIRECTION INPUT ;
    USE SIGNAL ;
    PORT
      LAYER M4 ;
        RECT  115.26 47.424 115.344 47.448 ;
    END
  END w_d[189]
  PIN w_d[18]
    DIRECTION INPUT ;
    USE SIGNAL ;
    PORT
      LAYER M4 ;
        RECT  115.26 10.032 115.344 10.056 ;
    END
  END w_d[18]
  PIN w_d[190]
    DIRECTION INPUT ;
    USE SIGNAL ;
    PORT
      LAYER M4 ;
        RECT  115.26 47.664 115.344 47.688 ;
    END
  END w_d[190]
  PIN w_d[191]
    DIRECTION INPUT ;
    USE SIGNAL ;
    PORT
      LAYER M4 ;
        RECT  115.26 47.856 115.344 47.88 ;
    END
  END w_d[191]
  PIN w_d[192]
    DIRECTION INPUT ;
    USE SIGNAL ;
    PORT
      LAYER M4 ;
        RECT  115.26 48.096 115.344 48.12 ;
    END
  END w_d[192]
  PIN w_d[193]
    DIRECTION INPUT ;
    USE SIGNAL ;
    PORT
      LAYER M4 ;
        RECT  115.26 48.336 115.344 48.36 ;
    END
  END w_d[193]
  PIN w_d[194]
    DIRECTION INPUT ;
    USE SIGNAL ;
    PORT
      LAYER M4 ;
        RECT  115.26 48.528 115.344 48.552 ;
    END
  END w_d[194]
  PIN w_d[195]
    DIRECTION INPUT ;
    USE SIGNAL ;
    PORT
      LAYER M4 ;
        RECT  115.26 48.768 115.344 48.792 ;
    END
  END w_d[195]
  PIN w_d[196]
    DIRECTION INPUT ;
    USE SIGNAL ;
    PORT
      LAYER M4 ;
        RECT  115.26 48.96 115.344 48.984 ;
    END
  END w_d[196]
  PIN w_d[197]
    DIRECTION INPUT ;
    USE SIGNAL ;
    PORT
      LAYER M4 ;
        RECT  115.26 49.2 115.344 49.224 ;
    END
  END w_d[197]
  PIN w_d[198]
    DIRECTION INPUT ;
    USE SIGNAL ;
    PORT
      LAYER M4 ;
        RECT  115.26 49.392 115.344 49.416 ;
    END
  END w_d[198]
  PIN w_d[199]
    DIRECTION INPUT ;
    USE SIGNAL ;
    PORT
      LAYER M4 ;
        RECT  115.26 49.632 115.344 49.656 ;
    END
  END w_d[199]
  PIN w_d[19]
    DIRECTION INPUT ;
    USE SIGNAL ;
    PORT
      LAYER M4 ;
        RECT  115.26 10.272 115.344 10.296 ;
    END
  END w_d[19]
  PIN w_d[1]
    DIRECTION INPUT ;
    USE SIGNAL ;
    PORT
      LAYER M4 ;
        RECT  115.26 6.336 115.344 6.36 ;
    END
  END w_d[1]
  PIN w_d[200]
    DIRECTION INPUT ;
    USE SIGNAL ;
    PORT
      LAYER M4 ;
        RECT  115.26 49.824 115.344 49.848 ;
    END
  END w_d[200]
  PIN w_d[201]
    DIRECTION INPUT ;
    USE SIGNAL ;
    PORT
      LAYER M4 ;
        RECT  115.26 50.064 115.344 50.088 ;
    END
  END w_d[201]
  PIN w_d[202]
    DIRECTION INPUT ;
    USE SIGNAL ;
    PORT
      LAYER M4 ;
        RECT  115.26 50.304 115.344 50.328 ;
    END
  END w_d[202]
  PIN w_d[203]
    DIRECTION INPUT ;
    USE SIGNAL ;
    PORT
      LAYER M4 ;
        RECT  115.26 50.496 115.344 50.52 ;
    END
  END w_d[203]
  PIN w_d[204]
    DIRECTION INPUT ;
    USE SIGNAL ;
    PORT
      LAYER M4 ;
        RECT  115.26 50.736 115.344 50.76 ;
    END
  END w_d[204]
  PIN w_d[205]
    DIRECTION INPUT ;
    USE SIGNAL ;
    PORT
      LAYER M4 ;
        RECT  115.26 50.928 115.344 50.952 ;
    END
  END w_d[205]
  PIN w_d[206]
    DIRECTION INPUT ;
    USE SIGNAL ;
    PORT
      LAYER M4 ;
        RECT  115.26 51.168 115.344 51.192 ;
    END
  END w_d[206]
  PIN w_d[207]
    DIRECTION INPUT ;
    USE SIGNAL ;
    PORT
      LAYER M4 ;
        RECT  115.26 51.36 115.344 51.384 ;
    END
  END w_d[207]
  PIN w_d[208]
    DIRECTION INPUT ;
    USE SIGNAL ;
    PORT
      LAYER M4 ;
        RECT  115.26 51.6 115.344 51.624 ;
    END
  END w_d[208]
  PIN w_d[209]
    DIRECTION INPUT ;
    USE SIGNAL ;
    PORT
      LAYER M4 ;
        RECT  115.26 51.84 115.344 51.864 ;
    END
  END w_d[209]
  PIN w_d[20]
    DIRECTION INPUT ;
    USE SIGNAL ;
    PORT
      LAYER M4 ;
        RECT  115.26 10.464 115.344 10.488 ;
    END
  END w_d[20]
  PIN w_d[210]
    DIRECTION INPUT ;
    USE SIGNAL ;
    PORT
      LAYER M4 ;
        RECT  115.26 52.032 115.344 52.056 ;
    END
  END w_d[210]
  PIN w_d[211]
    DIRECTION INPUT ;
    USE SIGNAL ;
    PORT
      LAYER M4 ;
        RECT  115.26 52.272 115.344 52.296 ;
    END
  END w_d[211]
  PIN w_d[212]
    DIRECTION INPUT ;
    USE SIGNAL ;
    PORT
      LAYER M4 ;
        RECT  115.26 52.464 115.344 52.488 ;
    END
  END w_d[212]
  PIN w_d[213]
    DIRECTION INPUT ;
    USE SIGNAL ;
    PORT
      LAYER M4 ;
        RECT  115.26 52.704 115.344 52.728 ;
    END
  END w_d[213]
  PIN w_d[214]
    DIRECTION INPUT ;
    USE SIGNAL ;
    PORT
      LAYER M4 ;
        RECT  115.26 52.896 115.344 52.92 ;
    END
  END w_d[214]
  PIN w_d[215]
    DIRECTION INPUT ;
    USE SIGNAL ;
    PORT
      LAYER M4 ;
        RECT  115.26 53.136 115.344 53.16 ;
    END
  END w_d[215]
  PIN w_d[216]
    DIRECTION INPUT ;
    USE SIGNAL ;
    PORT
      LAYER M4 ;
        RECT  115.26 53.328 115.344 53.352 ;
    END
  END w_d[216]
  PIN w_d[217]
    DIRECTION INPUT ;
    USE SIGNAL ;
    PORT
      LAYER M4 ;
        RECT  115.26 53.568 115.344 53.592 ;
    END
  END w_d[217]
  PIN w_d[218]
    DIRECTION INPUT ;
    USE SIGNAL ;
    PORT
      LAYER M4 ;
        RECT  115.26 53.808 115.344 53.832 ;
    END
  END w_d[218]
  PIN w_d[219]
    DIRECTION INPUT ;
    USE SIGNAL ;
    PORT
      LAYER M4 ;
        RECT  115.26 54 115.344 54.024 ;
    END
  END w_d[219]
  PIN w_d[21]
    DIRECTION INPUT ;
    USE SIGNAL ;
    PORT
      LAYER M4 ;
        RECT  115.26 10.704 115.344 10.728 ;
    END
  END w_d[21]
  PIN w_d[220]
    DIRECTION INPUT ;
    USE SIGNAL ;
    PORT
      LAYER M4 ;
        RECT  115.26 54.24 115.344 54.264 ;
    END
  END w_d[220]
  PIN w_d[221]
    DIRECTION INPUT ;
    USE SIGNAL ;
    PORT
      LAYER M4 ;
        RECT  115.26 54.432 115.344 54.456 ;
    END
  END w_d[221]
  PIN w_d[222]
    DIRECTION INPUT ;
    USE SIGNAL ;
    PORT
      LAYER M4 ;
        RECT  115.26 54.672 115.344 54.696 ;
    END
  END w_d[222]
  PIN w_d[223]
    DIRECTION INPUT ;
    USE SIGNAL ;
    PORT
      LAYER M4 ;
        RECT  115.26 54.864 115.344 54.888 ;
    END
  END w_d[223]
  PIN w_d[224]
    DIRECTION INPUT ;
    USE SIGNAL ;
    PORT
      LAYER M4 ;
        RECT  115.26 55.104 115.344 55.128 ;
    END
  END w_d[224]
  PIN w_d[225]
    DIRECTION INPUT ;
    USE SIGNAL ;
    PORT
      LAYER M4 ;
        RECT  115.26 55.296 115.344 55.32 ;
    END
  END w_d[225]
  PIN w_d[226]
    DIRECTION INPUT ;
    USE SIGNAL ;
    PORT
      LAYER M4 ;
        RECT  115.26 55.536 115.344 55.56 ;
    END
  END w_d[226]
  PIN w_d[227]
    DIRECTION INPUT ;
    USE SIGNAL ;
    PORT
      LAYER M4 ;
        RECT  115.26 55.728 115.344 55.752 ;
    END
  END w_d[227]
  PIN w_d[228]
    DIRECTION INPUT ;
    USE SIGNAL ;
    PORT
      LAYER M4 ;
        RECT  115.26 56.016 115.344 56.04 ;
    END
  END w_d[228]
  PIN w_d[229]
    DIRECTION INPUT ;
    USE SIGNAL ;
    PORT
      LAYER M4 ;
        RECT  115.26 56.208 115.344 56.232 ;
    END
  END w_d[229]
  PIN w_d[22]
    DIRECTION INPUT ;
    USE SIGNAL ;
    PORT
      LAYER M4 ;
        RECT  115.26 10.896 115.344 10.92 ;
    END
  END w_d[22]
  PIN w_d[230]
    DIRECTION INPUT ;
    USE SIGNAL ;
    PORT
      LAYER M4 ;
        RECT  115.26 56.4 115.344 56.424 ;
    END
  END w_d[230]
  PIN w_d[231]
    DIRECTION INPUT ;
    USE SIGNAL ;
    PORT
      LAYER M4 ;
        RECT  115.26 56.64 115.344 56.664 ;
    END
  END w_d[231]
  PIN w_d[232]
    DIRECTION INPUT ;
    USE SIGNAL ;
    PORT
      LAYER M4 ;
        RECT  115.26 56.832 115.344 56.856 ;
    END
  END w_d[232]
  PIN w_d[233]
    DIRECTION INPUT ;
    USE SIGNAL ;
    PORT
      LAYER M4 ;
        RECT  115.26 57.072 115.344 57.096 ;
    END
  END w_d[233]
  PIN w_d[234]
    DIRECTION INPUT ;
    USE SIGNAL ;
    PORT
      LAYER M4 ;
        RECT  115.26 57.264 115.344 57.288 ;
    END
  END w_d[234]
  PIN w_d[235]
    DIRECTION INPUT ;
    USE SIGNAL ;
    PORT
      LAYER M4 ;
        RECT  115.26 57.456 115.344 57.48 ;
    END
  END w_d[235]
  PIN w_d[236]
    DIRECTION INPUT ;
    USE SIGNAL ;
    PORT
      LAYER M4 ;
        RECT  115.26 57.744 115.344 57.768 ;
    END
  END w_d[236]
  PIN w_d[237]
    DIRECTION INPUT ;
    USE SIGNAL ;
    PORT
      LAYER M4 ;
        RECT  115.26 57.936 115.344 57.96 ;
    END
  END w_d[237]
  PIN w_d[238]
    DIRECTION INPUT ;
    USE SIGNAL ;
    PORT
      LAYER M4 ;
        RECT  115.26 58.176 115.344 58.2 ;
    END
  END w_d[238]
  PIN w_d[239]
    DIRECTION INPUT ;
    USE SIGNAL ;
    PORT
      LAYER M4 ;
        RECT  115.26 58.368 115.344 58.392 ;
    END
  END w_d[239]
  PIN w_d[23]
    DIRECTION INPUT ;
    USE SIGNAL ;
    PORT
      LAYER M4 ;
        RECT  115.26 11.136 115.344 11.16 ;
    END
  END w_d[23]
  PIN w_d[240]
    DIRECTION INPUT ;
    USE SIGNAL ;
    PORT
      LAYER M4 ;
        RECT  115.26 58.608 115.344 58.632 ;
    END
  END w_d[240]
  PIN w_d[241]
    DIRECTION INPUT ;
    USE SIGNAL ;
    PORT
      LAYER M4 ;
        RECT  115.26 58.8 115.344 58.824 ;
    END
  END w_d[241]
  PIN w_d[242]
    DIRECTION INPUT ;
    USE SIGNAL ;
    PORT
      LAYER M4 ;
        RECT  115.26 58.992 115.344 59.016 ;
    END
  END w_d[242]
  PIN w_d[243]
    DIRECTION INPUT ;
    USE SIGNAL ;
    PORT
      LAYER M4 ;
        RECT  115.26 59.28 115.344 59.304 ;
    END
  END w_d[243]
  PIN w_d[244]
    DIRECTION INPUT ;
    USE SIGNAL ;
    PORT
      LAYER M4 ;
        RECT  115.26 59.472 115.344 59.496 ;
    END
  END w_d[244]
  PIN w_d[245]
    DIRECTION INPUT ;
    USE SIGNAL ;
    PORT
      LAYER M4 ;
        RECT  115.26 59.712 115.344 59.736 ;
    END
  END w_d[245]
  PIN w_d[246]
    DIRECTION INPUT ;
    USE SIGNAL ;
    PORT
      LAYER M4 ;
        RECT  115.26 59.904 115.344 59.928 ;
    END
  END w_d[246]
  PIN w_d[247]
    DIRECTION INPUT ;
    USE SIGNAL ;
    PORT
      LAYER M4 ;
        RECT  115.26 60.096 115.344 60.12 ;
    END
  END w_d[247]
  PIN w_d[248]
    DIRECTION INPUT ;
    USE SIGNAL ;
    PORT
      LAYER M4 ;
        RECT  115.26 60.336 115.344 60.36 ;
    END
  END w_d[248]
  PIN w_d[249]
    DIRECTION INPUT ;
    USE SIGNAL ;
    PORT
      LAYER M4 ;
        RECT  115.26 60.528 115.344 60.552 ;
    END
  END w_d[249]
  PIN w_d[24]
    DIRECTION INPUT ;
    USE SIGNAL ;
    PORT
      LAYER M4 ;
        RECT  115.26 11.328 115.344 11.352 ;
    END
  END w_d[24]
  PIN w_d[250]
    DIRECTION INPUT ;
    USE SIGNAL ;
    PORT
      LAYER M4 ;
        RECT  115.26 60.816 115.344 60.84 ;
    END
  END w_d[250]
  PIN w_d[251]
    DIRECTION INPUT ;
    USE SIGNAL ;
    PORT
      LAYER M4 ;
        RECT  115.26 61.008 115.344 61.032 ;
    END
  END w_d[251]
  PIN w_d[252]
    DIRECTION INPUT ;
    USE SIGNAL ;
    PORT
      LAYER M4 ;
        RECT  115.26 61.248 115.344 61.272 ;
    END
  END w_d[252]
  PIN w_d[253]
    DIRECTION INPUT ;
    USE SIGNAL ;
    PORT
      LAYER M4 ;
        RECT  115.26 61.44 115.344 61.464 ;
    END
  END w_d[253]
  PIN w_d[254]
    DIRECTION INPUT ;
    USE SIGNAL ;
    PORT
      LAYER M4 ;
        RECT  115.26 61.632 115.344 61.656 ;
    END
  END w_d[254]
  PIN w_d[255]
    DIRECTION INPUT ;
    USE SIGNAL ;
    PORT
      LAYER M4 ;
        RECT  115.26 61.872 115.344 61.896 ;
    END
  END w_d[255]
  PIN w_d[25]
    DIRECTION INPUT ;
    USE SIGNAL ;
    PORT
      LAYER M4 ;
        RECT  115.26 11.568 115.344 11.592 ;
    END
  END w_d[25]
  PIN w_d[26]
    DIRECTION INPUT ;
    USE SIGNAL ;
    PORT
      LAYER M4 ;
        RECT  115.26 11.808 115.344 11.832 ;
    END
  END w_d[26]
  PIN w_d[27]
    DIRECTION INPUT ;
    USE SIGNAL ;
    PORT
      LAYER M4 ;
        RECT  115.26 12 115.344 12.024 ;
    END
  END w_d[27]
  PIN w_d[28]
    DIRECTION INPUT ;
    USE SIGNAL ;
    PORT
      LAYER M4 ;
        RECT  115.26 12.24 115.344 12.264 ;
    END
  END w_d[28]
  PIN w_d[29]
    DIRECTION INPUT ;
    USE SIGNAL ;
    PORT
      LAYER M4 ;
        RECT  115.26 12.432 115.344 12.456 ;
    END
  END w_d[29]
  PIN w_d[2]
    DIRECTION INPUT ;
    USE SIGNAL ;
    PORT
      LAYER M4 ;
        RECT  115.26 6.528 115.344 6.552 ;
    END
  END w_d[2]
  PIN w_d[30]
    DIRECTION INPUT ;
    USE SIGNAL ;
    PORT
      LAYER M4 ;
        RECT  115.26 12.672 115.344 12.696 ;
    END
  END w_d[30]
  PIN w_d[31]
    DIRECTION INPUT ;
    USE SIGNAL ;
    PORT
      LAYER M4 ;
        RECT  115.26 12.864 115.344 12.888 ;
    END
  END w_d[31]
  PIN w_d[32]
    DIRECTION INPUT ;
    USE SIGNAL ;
    PORT
      LAYER M4 ;
        RECT  115.26 13.104 115.344 13.128 ;
    END
  END w_d[32]
  PIN w_d[33]
    DIRECTION INPUT ;
    USE SIGNAL ;
    PORT
      LAYER M4 ;
        RECT  115.26 13.296 115.344 13.32 ;
    END
  END w_d[33]
  PIN w_d[34]
    DIRECTION INPUT ;
    USE SIGNAL ;
    PORT
      LAYER M4 ;
        RECT  115.26 13.488 115.344 13.512 ;
    END
  END w_d[34]
  PIN w_d[35]
    DIRECTION INPUT ;
    USE SIGNAL ;
    PORT
      LAYER M4 ;
        RECT  115.26 13.776 115.344 13.8 ;
    END
  END w_d[35]
  PIN w_d[36]
    DIRECTION INPUT ;
    USE SIGNAL ;
    PORT
      LAYER M4 ;
        RECT  115.26 13.968 115.344 13.992 ;
    END
  END w_d[36]
  PIN w_d[37]
    DIRECTION INPUT ;
    USE SIGNAL ;
    PORT
      LAYER M4 ;
        RECT  115.26 14.208 115.344 14.232 ;
    END
  END w_d[37]
  PIN w_d[38]
    DIRECTION INPUT ;
    USE SIGNAL ;
    PORT
      LAYER M4 ;
        RECT  115.26 14.4 115.344 14.424 ;
    END
  END w_d[38]
  PIN w_d[39]
    DIRECTION INPUT ;
    USE SIGNAL ;
    PORT
      LAYER M4 ;
        RECT  115.26 14.64 115.344 14.664 ;
    END
  END w_d[39]
  PIN w_d[3]
    DIRECTION INPUT ;
    USE SIGNAL ;
    PORT
      LAYER M4 ;
        RECT  115.26 6.768 115.344 6.792 ;
    END
  END w_d[3]
  PIN w_d[40]
    DIRECTION INPUT ;
    USE SIGNAL ;
    PORT
      LAYER M4 ;
        RECT  115.26 14.832 115.344 14.856 ;
    END
  END w_d[40]
  PIN w_d[41]
    DIRECTION INPUT ;
    USE SIGNAL ;
    PORT
      LAYER M4 ;
        RECT  115.26 15.024 115.344 15.048 ;
    END
  END w_d[41]
  PIN w_d[42]
    DIRECTION INPUT ;
    USE SIGNAL ;
    PORT
      LAYER M4 ;
        RECT  115.26 15.312 115.344 15.336 ;
    END
  END w_d[42]
  PIN w_d[43]
    DIRECTION INPUT ;
    USE SIGNAL ;
    PORT
      LAYER M4 ;
        RECT  115.26 15.504 115.344 15.528 ;
    END
  END w_d[43]
  PIN w_d[44]
    DIRECTION INPUT ;
    USE SIGNAL ;
    PORT
      LAYER M4 ;
        RECT  115.26 15.744 115.344 15.768 ;
    END
  END w_d[44]
  PIN w_d[45]
    DIRECTION INPUT ;
    USE SIGNAL ;
    PORT
      LAYER M4 ;
        RECT  115.26 15.936 115.344 15.96 ;
    END
  END w_d[45]
  PIN w_d[46]
    DIRECTION INPUT ;
    USE SIGNAL ;
    PORT
      LAYER M4 ;
        RECT  115.26 16.128 115.344 16.152 ;
    END
  END w_d[46]
  PIN w_d[47]
    DIRECTION INPUT ;
    USE SIGNAL ;
    PORT
      LAYER M4 ;
        RECT  115.26 16.368 115.344 16.392 ;
    END
  END w_d[47]
  PIN w_d[48]
    DIRECTION INPUT ;
    USE SIGNAL ;
    PORT
      LAYER M4 ;
        RECT  115.26 16.56 115.344 16.584 ;
    END
  END w_d[48]
  PIN w_d[49]
    DIRECTION INPUT ;
    USE SIGNAL ;
    PORT
      LAYER M4 ;
        RECT  115.26 16.848 115.344 16.872 ;
    END
  END w_d[49]
  PIN w_d[4]
    DIRECTION INPUT ;
    USE SIGNAL ;
    PORT
      LAYER M4 ;
        RECT  115.26 6.96 115.344 6.984 ;
    END
  END w_d[4]
  PIN w_d[50]
    DIRECTION INPUT ;
    USE SIGNAL ;
    PORT
      LAYER M4 ;
        RECT  115.26 17.04 115.344 17.064 ;
    END
  END w_d[50]
  PIN w_d[51]
    DIRECTION INPUT ;
    USE SIGNAL ;
    PORT
      LAYER M4 ;
        RECT  115.26 17.28 115.344 17.304 ;
    END
  END w_d[51]
  PIN w_d[52]
    DIRECTION INPUT ;
    USE SIGNAL ;
    PORT
      LAYER M4 ;
        RECT  115.26 17.472 115.344 17.496 ;
    END
  END w_d[52]
  PIN w_d[53]
    DIRECTION INPUT ;
    USE SIGNAL ;
    PORT
      LAYER M4 ;
        RECT  115.26 17.664 115.344 17.688 ;
    END
  END w_d[53]
  PIN w_d[54]
    DIRECTION INPUT ;
    USE SIGNAL ;
    PORT
      LAYER M4 ;
        RECT  115.26 17.904 115.344 17.928 ;
    END
  END w_d[54]
  PIN w_d[55]
    DIRECTION INPUT ;
    USE SIGNAL ;
    PORT
      LAYER M4 ;
        RECT  115.26 18.096 115.344 18.12 ;
    END
  END w_d[55]
  PIN w_d[56]
    DIRECTION INPUT ;
    USE SIGNAL ;
    PORT
      LAYER M4 ;
        RECT  115.26 18.384 115.344 18.408 ;
    END
  END w_d[56]
  PIN w_d[57]
    DIRECTION INPUT ;
    USE SIGNAL ;
    PORT
      LAYER M4 ;
        RECT  115.26 18.576 115.344 18.6 ;
    END
  END w_d[57]
  PIN w_d[58]
    DIRECTION INPUT ;
    USE SIGNAL ;
    PORT
      LAYER M4 ;
        RECT  115.26 18.768 115.344 18.792 ;
    END
  END w_d[58]
  PIN w_d[59]
    DIRECTION INPUT ;
    USE SIGNAL ;
    PORT
      LAYER M4 ;
        RECT  115.26 19.008 115.344 19.032 ;
    END
  END w_d[59]
  PIN w_d[5]
    DIRECTION INPUT ;
    USE SIGNAL ;
    PORT
      LAYER M4 ;
        RECT  115.26 7.2 115.344 7.224 ;
    END
  END w_d[5]
  PIN w_d[60]
    DIRECTION INPUT ;
    USE SIGNAL ;
    PORT
      LAYER M4 ;
        RECT  115.26 19.2 115.344 19.224 ;
    END
  END w_d[60]
  PIN w_d[61]
    DIRECTION INPUT ;
    USE SIGNAL ;
    PORT
      LAYER M4 ;
        RECT  115.26 19.44 115.344 19.464 ;
    END
  END w_d[61]
  PIN w_d[62]
    DIRECTION INPUT ;
    USE SIGNAL ;
    PORT
      LAYER M4 ;
        RECT  115.26 19.632 115.344 19.656 ;
    END
  END w_d[62]
  PIN w_d[63]
    DIRECTION INPUT ;
    USE SIGNAL ;
    PORT
      LAYER M4 ;
        RECT  115.26 19.92 115.344 19.944 ;
    END
  END w_d[63]
  PIN w_d[64]
    DIRECTION INPUT ;
    USE SIGNAL ;
    PORT
      LAYER M4 ;
        RECT  115.26 20.112 115.344 20.136 ;
    END
  END w_d[64]
  PIN w_d[65]
    DIRECTION INPUT ;
    USE SIGNAL ;
    PORT
      LAYER M4 ;
        RECT  115.26 20.304 115.344 20.328 ;
    END
  END w_d[65]
  PIN w_d[66]
    DIRECTION INPUT ;
    USE SIGNAL ;
    PORT
      LAYER M4 ;
        RECT  115.26 20.544 115.344 20.568 ;
    END
  END w_d[66]
  PIN w_d[67]
    DIRECTION INPUT ;
    USE SIGNAL ;
    PORT
      LAYER M4 ;
        RECT  115.26 20.736 115.344 20.76 ;
    END
  END w_d[67]
  PIN w_d[68]
    DIRECTION INPUT ;
    USE SIGNAL ;
    PORT
      LAYER M4 ;
        RECT  115.26 20.976 115.344 21 ;
    END
  END w_d[68]
  PIN w_d[69]
    DIRECTION INPUT ;
    USE SIGNAL ;
    PORT
      LAYER M4 ;
        RECT  115.26 21.168 115.344 21.192 ;
    END
  END w_d[69]
  PIN w_d[6]
    DIRECTION INPUT ;
    USE SIGNAL ;
    PORT
      LAYER M4 ;
        RECT  115.26 7.392 115.344 7.416 ;
    END
  END w_d[6]
  PIN w_d[70]
    DIRECTION INPUT ;
    USE SIGNAL ;
    PORT
      LAYER M4 ;
        RECT  115.26 21.408 115.344 21.432 ;
    END
  END w_d[70]
  PIN w_d[71]
    DIRECTION INPUT ;
    USE SIGNAL ;
    PORT
      LAYER M4 ;
        RECT  115.26 21.648 115.344 21.672 ;
    END
  END w_d[71]
  PIN w_d[72]
    DIRECTION INPUT ;
    USE SIGNAL ;
    PORT
      LAYER M4 ;
        RECT  115.26 21.84 115.344 21.864 ;
    END
  END w_d[72]
  PIN w_d[73]
    DIRECTION INPUT ;
    USE SIGNAL ;
    PORT
      LAYER M4 ;
        RECT  115.26 22.08 115.344 22.104 ;
    END
  END w_d[73]
  PIN w_d[74]
    DIRECTION INPUT ;
    USE SIGNAL ;
    PORT
      LAYER M4 ;
        RECT  115.26 22.272 115.344 22.296 ;
    END
  END w_d[74]
  PIN w_d[75]
    DIRECTION INPUT ;
    USE SIGNAL ;
    PORT
      LAYER M4 ;
        RECT  115.26 22.512 115.344 22.536 ;
    END
  END w_d[75]
  PIN w_d[76]
    DIRECTION INPUT ;
    USE SIGNAL ;
    PORT
      LAYER M4 ;
        RECT  115.26 22.704 115.344 22.728 ;
    END
  END w_d[76]
  PIN w_d[77]
    DIRECTION INPUT ;
    USE SIGNAL ;
    PORT
      LAYER M4 ;
        RECT  115.26 22.944 115.344 22.968 ;
    END
  END w_d[77]
  PIN w_d[78]
    DIRECTION INPUT ;
    USE SIGNAL ;
    PORT
      LAYER M4 ;
        RECT  115.26 23.184 115.344 23.208 ;
    END
  END w_d[78]
  PIN w_d[79]
    DIRECTION INPUT ;
    USE SIGNAL ;
    PORT
      LAYER M4 ;
        RECT  115.26 23.376 115.344 23.4 ;
    END
  END w_d[79]
  PIN w_d[7]
    DIRECTION INPUT ;
    USE SIGNAL ;
    PORT
      LAYER M4 ;
        RECT  115.26 7.632 115.344 7.656 ;
    END
  END w_d[7]
  PIN w_d[80]
    DIRECTION INPUT ;
    USE SIGNAL ;
    PORT
      LAYER M4 ;
        RECT  115.26 23.616 115.344 23.64 ;
    END
  END w_d[80]
  PIN w_d[81]
    DIRECTION INPUT ;
    USE SIGNAL ;
    PORT
      LAYER M4 ;
        RECT  115.26 23.808 115.344 23.832 ;
    END
  END w_d[81]
  PIN w_d[82]
    DIRECTION INPUT ;
    USE SIGNAL ;
    PORT
      LAYER M4 ;
        RECT  115.26 24.048 115.344 24.072 ;
    END
  END w_d[82]
  PIN w_d[83]
    DIRECTION INPUT ;
    USE SIGNAL ;
    PORT
      LAYER M4 ;
        RECT  115.26 24.24 115.344 24.264 ;
    END
  END w_d[83]
  PIN w_d[84]
    DIRECTION INPUT ;
    USE SIGNAL ;
    PORT
      LAYER M4 ;
        RECT  115.26 24.48 115.344 24.504 ;
    END
  END w_d[84]
  PIN w_d[85]
    DIRECTION INPUT ;
    USE SIGNAL ;
    PORT
      LAYER M4 ;
        RECT  115.26 24.672 115.344 24.696 ;
    END
  END w_d[85]
  PIN w_d[86]
    DIRECTION INPUT ;
    USE SIGNAL ;
    PORT
      LAYER M4 ;
        RECT  115.26 24.912 115.344 24.936 ;
    END
  END w_d[86]
  PIN w_d[87]
    DIRECTION INPUT ;
    USE SIGNAL ;
    PORT
      LAYER M4 ;
        RECT  115.26 25.152 115.344 25.176 ;
    END
  END w_d[87]
  PIN w_d[88]
    DIRECTION INPUT ;
    USE SIGNAL ;
    PORT
      LAYER M4 ;
        RECT  115.26 25.344 115.344 25.368 ;
    END
  END w_d[88]
  PIN w_d[89]
    DIRECTION INPUT ;
    USE SIGNAL ;
    PORT
      LAYER M4 ;
        RECT  115.26 25.584 115.344 25.608 ;
    END
  END w_d[89]
  PIN w_d[8]
    DIRECTION INPUT ;
    USE SIGNAL ;
    PORT
      LAYER M4 ;
        RECT  115.26 7.824 115.344 7.848 ;
    END
  END w_d[8]
  PIN w_d[90]
    DIRECTION INPUT ;
    USE SIGNAL ;
    PORT
      LAYER M4 ;
        RECT  115.26 25.776 115.344 25.8 ;
    END
  END w_d[90]
  PIN w_d[91]
    DIRECTION INPUT ;
    USE SIGNAL ;
    PORT
      LAYER M4 ;
        RECT  115.26 26.016 115.344 26.04 ;
    END
  END w_d[91]
  PIN w_d[92]
    DIRECTION INPUT ;
    USE SIGNAL ;
    PORT
      LAYER M4 ;
        RECT  115.26 26.208 115.344 26.232 ;
    END
  END w_d[92]
  PIN w_d[93]
    DIRECTION INPUT ;
    USE SIGNAL ;
    PORT
      LAYER M4 ;
        RECT  115.26 26.448 115.344 26.472 ;
    END
  END w_d[93]
  PIN w_d[94]
    DIRECTION INPUT ;
    USE SIGNAL ;
    PORT
      LAYER M4 ;
        RECT  115.26 26.64 115.344 26.664 ;
    END
  END w_d[94]
  PIN w_d[95]
    DIRECTION INPUT ;
    USE SIGNAL ;
    PORT
      LAYER M4 ;
        RECT  115.26 26.88 115.344 26.904 ;
    END
  END w_d[95]
  PIN w_d[96]
    DIRECTION INPUT ;
    USE SIGNAL ;
    PORT
      LAYER M4 ;
        RECT  115.26 27.072 115.344 27.096 ;
    END
  END w_d[96]
  PIN w_d[97]
    DIRECTION INPUT ;
    USE SIGNAL ;
    PORT
      LAYER M4 ;
        RECT  115.26 27.312 115.344 27.336 ;
    END
  END w_d[97]
  PIN w_d[98]
    DIRECTION INPUT ;
    USE SIGNAL ;
    PORT
      LAYER M4 ;
        RECT  115.26 27.504 115.344 27.528 ;
    END
  END w_d[98]
  PIN w_d[99]
    DIRECTION INPUT ;
    USE SIGNAL ;
    PORT
      LAYER M4 ;
        RECT  115.26 27.792 115.344 27.816 ;
    END
  END w_d[99]
  PIN w_d[9]
    DIRECTION INPUT ;
    USE SIGNAL ;
    PORT
      LAYER M4 ;
        RECT  115.26 8.064 115.344 8.088 ;
    END
  END w_d[9]
  PIN x_d[0]
    DIRECTION INPUT ;
    USE SIGNAL ;
    PORT
      LAYER M4 ;
        RECT  115.26 78.096 115.344 78.12 ;
    END
  END x_d[0]
  PIN x_d[100]
    DIRECTION INPUT ;
    USE SIGNAL ;
    PORT
      LAYER M4 ;
        RECT  115.26 95.232 115.344 95.256 ;
    END
  END x_d[100]
  PIN x_d[101]
    DIRECTION INPUT ;
    USE SIGNAL ;
    PORT
      LAYER M4 ;
        RECT  115.26 95.424 115.344 95.448 ;
    END
  END x_d[101]
  PIN x_d[102]
    DIRECTION INPUT ;
    USE SIGNAL ;
    PORT
      LAYER M4 ;
        RECT  115.26 95.616 115.344 95.64 ;
    END
  END x_d[102]
  PIN x_d[103]
    DIRECTION INPUT ;
    USE SIGNAL ;
    PORT
      LAYER M4 ;
        RECT  115.26 95.76 115.344 95.784 ;
    END
  END x_d[103]
  PIN x_d[104]
    DIRECTION INPUT ;
    USE SIGNAL ;
    PORT
      LAYER M4 ;
        RECT  115.26 95.952 115.344 95.976 ;
    END
  END x_d[104]
  PIN x_d[105]
    DIRECTION INPUT ;
    USE SIGNAL ;
    PORT
      LAYER M4 ;
        RECT  115.26 96.144 115.344 96.168 ;
    END
  END x_d[105]
  PIN x_d[106]
    DIRECTION INPUT ;
    USE SIGNAL ;
    PORT
      LAYER M4 ;
        RECT  115.26 96.336 115.344 96.36 ;
    END
  END x_d[106]
  PIN x_d[107]
    DIRECTION INPUT ;
    USE SIGNAL ;
    PORT
      LAYER M4 ;
        RECT  115.26 96.432 115.344 96.456 ;
    END
  END x_d[107]
  PIN x_d[108]
    DIRECTION INPUT ;
    USE SIGNAL ;
    PORT
      LAYER M4 ;
        RECT  115.26 96.624 115.344 96.648 ;
    END
  END x_d[108]
  PIN x_d[109]
    DIRECTION INPUT ;
    USE SIGNAL ;
    PORT
      LAYER M4 ;
        RECT  115.26 96.816 115.344 96.84 ;
    END
  END x_d[109]
  PIN x_d[10]
    DIRECTION INPUT ;
    USE SIGNAL ;
    PORT
      LAYER M4 ;
        RECT  115.26 79.776 115.344 79.8 ;
    END
  END x_d[10]
  PIN x_d[110]
    DIRECTION INPUT ;
    USE SIGNAL ;
    PORT
      LAYER M4 ;
        RECT  115.26 96.96 115.344 96.984 ;
    END
  END x_d[110]
  PIN x_d[111]
    DIRECTION INPUT ;
    USE SIGNAL ;
    PORT
      LAYER M4 ;
        RECT  115.26 97.152 115.344 97.176 ;
    END
  END x_d[111]
  PIN x_d[112]
    DIRECTION INPUT ;
    USE SIGNAL ;
    PORT
      LAYER M4 ;
        RECT  115.26 97.344 115.344 97.368 ;
    END
  END x_d[112]
  PIN x_d[113]
    DIRECTION INPUT ;
    USE SIGNAL ;
    PORT
      LAYER M4 ;
        RECT  115.26 97.488 115.344 97.512 ;
    END
  END x_d[113]
  PIN x_d[114]
    DIRECTION INPUT ;
    USE SIGNAL ;
    PORT
      LAYER M4 ;
        RECT  115.26 97.68 115.344 97.704 ;
    END
  END x_d[114]
  PIN x_d[115]
    DIRECTION INPUT ;
    USE SIGNAL ;
    PORT
      LAYER M4 ;
        RECT  115.26 97.872 115.344 97.896 ;
    END
  END x_d[115]
  PIN x_d[116]
    DIRECTION INPUT ;
    USE SIGNAL ;
    PORT
      LAYER M4 ;
        RECT  115.26 97.968 115.344 97.992 ;
    END
  END x_d[116]
  PIN x_d[117]
    DIRECTION INPUT ;
    USE SIGNAL ;
    PORT
      LAYER M4 ;
        RECT  115.26 98.16 115.344 98.184 ;
    END
  END x_d[117]
  PIN x_d[118]
    DIRECTION INPUT ;
    USE SIGNAL ;
    PORT
      LAYER M4 ;
        RECT  115.26 98.352 115.344 98.376 ;
    END
  END x_d[118]
  PIN x_d[119]
    DIRECTION INPUT ;
    USE SIGNAL ;
    PORT
      LAYER M4 ;
        RECT  115.26 98.496 115.344 98.52 ;
    END
  END x_d[119]
  PIN x_d[11]
    DIRECTION INPUT ;
    USE SIGNAL ;
    PORT
      LAYER M4 ;
        RECT  115.26 79.968 115.344 79.992 ;
    END
  END x_d[11]
  PIN x_d[120]
    DIRECTION INPUT ;
    USE SIGNAL ;
    PORT
      LAYER M4 ;
        RECT  115.26 98.688 115.344 98.712 ;
    END
  END x_d[120]
  PIN x_d[121]
    DIRECTION INPUT ;
    USE SIGNAL ;
    PORT
      LAYER M4 ;
        RECT  115.26 98.88 115.344 98.904 ;
    END
  END x_d[121]
  PIN x_d[122]
    DIRECTION INPUT ;
    USE SIGNAL ;
    PORT
      LAYER M4 ;
        RECT  115.26 99.024 115.344 99.048 ;
    END
  END x_d[122]
  PIN x_d[123]
    DIRECTION INPUT ;
    USE SIGNAL ;
    PORT
      LAYER M4 ;
        RECT  115.26 99.216 115.344 99.24 ;
    END
  END x_d[123]
  PIN x_d[124]
    DIRECTION INPUT ;
    USE SIGNAL ;
    PORT
      LAYER M4 ;
        RECT  115.26 99.408 115.344 99.432 ;
    END
  END x_d[124]
  PIN x_d[125]
    DIRECTION INPUT ;
    USE SIGNAL ;
    PORT
      LAYER M4 ;
        RECT  115.26 99.6 115.344 99.624 ;
    END
  END x_d[125]
  PIN x_d[126]
    DIRECTION INPUT ;
    USE SIGNAL ;
    PORT
      LAYER M4 ;
        RECT  115.26 99.696 115.344 99.72 ;
    END
  END x_d[126]
  PIN x_d[127]
    DIRECTION INPUT ;
    USE SIGNAL ;
    PORT
      LAYER M4 ;
        RECT  115.26 99.888 115.344 99.912 ;
    END
  END x_d[127]
  PIN x_d[12]
    DIRECTION INPUT ;
    USE SIGNAL ;
    PORT
      LAYER M4 ;
        RECT  115.26 80.16 115.344 80.184 ;
    END
  END x_d[12]
  PIN x_d[13]
    DIRECTION INPUT ;
    USE SIGNAL ;
    PORT
      LAYER M4 ;
        RECT  115.26 80.304 115.344 80.328 ;
    END
  END x_d[13]
  PIN x_d[14]
    DIRECTION INPUT ;
    USE SIGNAL ;
    PORT
      LAYER M4 ;
        RECT  115.26 80.496 115.344 80.52 ;
    END
  END x_d[14]
  PIN x_d[15]
    DIRECTION INPUT ;
    USE SIGNAL ;
    PORT
      LAYER M4 ;
        RECT  115.26 80.64 115.344 80.664 ;
    END
  END x_d[15]
  PIN x_d[16]
    DIRECTION INPUT ;
    USE SIGNAL ;
    PORT
      LAYER M4 ;
        RECT  115.26 80.832 115.344 80.856 ;
    END
  END x_d[16]
  PIN x_d[17]
    DIRECTION INPUT ;
    USE SIGNAL ;
    PORT
      LAYER M4 ;
        RECT  115.26 80.976 115.344 81 ;
    END
  END x_d[17]
  PIN x_d[18]
    DIRECTION INPUT ;
    USE SIGNAL ;
    PORT
      LAYER M4 ;
        RECT  115.26 81.168 115.344 81.192 ;
    END
  END x_d[18]
  PIN x_d[19]
    DIRECTION INPUT ;
    USE SIGNAL ;
    PORT
      LAYER M4 ;
        RECT  115.26 81.36 115.344 81.384 ;
    END
  END x_d[19]
  PIN x_d[1]
    DIRECTION INPUT ;
    USE SIGNAL ;
    PORT
      LAYER M4 ;
        RECT  115.26 78.24 115.344 78.264 ;
    END
  END x_d[1]
  PIN x_d[20]
    DIRECTION INPUT ;
    USE SIGNAL ;
    PORT
      LAYER M4 ;
        RECT  115.26 81.504 115.344 81.528 ;
    END
  END x_d[20]
  PIN x_d[21]
    DIRECTION INPUT ;
    USE SIGNAL ;
    PORT
      LAYER M4 ;
        RECT  115.26 81.696 115.344 81.72 ;
    END
  END x_d[21]
  PIN x_d[22]
    DIRECTION INPUT ;
    USE SIGNAL ;
    PORT
      LAYER M4 ;
        RECT  115.26 81.84 115.344 81.864 ;
    END
  END x_d[22]
  PIN x_d[23]
    DIRECTION INPUT ;
    USE SIGNAL ;
    PORT
      LAYER M4 ;
        RECT  115.26 82.032 115.344 82.056 ;
    END
  END x_d[23]
  PIN x_d[24]
    DIRECTION INPUT ;
    USE SIGNAL ;
    PORT
      LAYER M4 ;
        RECT  115.26 82.176 115.344 82.2 ;
    END
  END x_d[24]
  PIN x_d[25]
    DIRECTION INPUT ;
    USE SIGNAL ;
    PORT
      LAYER M4 ;
        RECT  115.26 82.368 115.344 82.392 ;
    END
  END x_d[25]
  PIN x_d[26]
    DIRECTION INPUT ;
    USE SIGNAL ;
    PORT
      LAYER M4 ;
        RECT  115.26 82.56 115.344 82.584 ;
    END
  END x_d[26]
  PIN x_d[27]
    DIRECTION INPUT ;
    USE SIGNAL ;
    PORT
      LAYER M4 ;
        RECT  115.26 82.704 115.344 82.728 ;
    END
  END x_d[27]
  PIN x_d[28]
    DIRECTION INPUT ;
    USE SIGNAL ;
    PORT
      LAYER M4 ;
        RECT  115.26 82.896 115.344 82.92 ;
    END
  END x_d[28]
  PIN x_d[29]
    DIRECTION INPUT ;
    USE SIGNAL ;
    PORT
      LAYER M4 ;
        RECT  115.26 83.04 115.344 83.064 ;
    END
  END x_d[29]
  PIN x_d[2]
    DIRECTION INPUT ;
    USE SIGNAL ;
    PORT
      LAYER M4 ;
        RECT  115.26 78.432 115.344 78.456 ;
    END
  END x_d[2]
  PIN x_d[30]
    DIRECTION INPUT ;
    USE SIGNAL ;
    PORT
      LAYER M4 ;
        RECT  115.26 83.232 115.344 83.256 ;
    END
  END x_d[30]
  PIN x_d[31]
    DIRECTION INPUT ;
    USE SIGNAL ;
    PORT
      LAYER M4 ;
        RECT  115.26 83.424 115.344 83.448 ;
    END
  END x_d[31]
  PIN x_d[32]
    DIRECTION INPUT ;
    USE SIGNAL ;
    PORT
      LAYER M4 ;
        RECT  115.26 83.568 115.344 83.592 ;
    END
  END x_d[32]
  PIN x_d[33]
    DIRECTION INPUT ;
    USE SIGNAL ;
    PORT
      LAYER M4 ;
        RECT  115.26 83.712 115.344 83.736 ;
    END
  END x_d[33]
  PIN x_d[34]
    DIRECTION INPUT ;
    USE SIGNAL ;
    PORT
      LAYER M4 ;
        RECT  115.26 83.904 115.344 83.928 ;
    END
  END x_d[34]
  PIN x_d[35]
    DIRECTION INPUT ;
    USE SIGNAL ;
    PORT
      LAYER M4 ;
        RECT  115.26 84.096 115.344 84.12 ;
    END
  END x_d[35]
  PIN x_d[36]
    DIRECTION INPUT ;
    USE SIGNAL ;
    PORT
      LAYER M4 ;
        RECT  115.26 84.288 115.344 84.312 ;
    END
  END x_d[36]
  PIN x_d[37]
    DIRECTION INPUT ;
    USE SIGNAL ;
    PORT
      LAYER M4 ;
        RECT  115.26 84.432 115.344 84.456 ;
    END
  END x_d[37]
  PIN x_d[38]
    DIRECTION INPUT ;
    USE SIGNAL ;
    PORT
      LAYER M4 ;
        RECT  115.26 84.624 115.344 84.648 ;
    END
  END x_d[38]
  PIN x_d[39]
    DIRECTION INPUT ;
    USE SIGNAL ;
    PORT
      LAYER M4 ;
        RECT  115.26 84.816 115.344 84.84 ;
    END
  END x_d[39]
  PIN x_d[3]
    DIRECTION INPUT ;
    USE SIGNAL ;
    PORT
      LAYER M4 ;
        RECT  115.26 78.576 115.344 78.6 ;
    END
  END x_d[3]
  PIN x_d[40]
    DIRECTION INPUT ;
    USE SIGNAL ;
    PORT
      LAYER M4 ;
        RECT  115.26 84.912 115.344 84.936 ;
    END
  END x_d[40]
  PIN x_d[41]
    DIRECTION INPUT ;
    USE SIGNAL ;
    PORT
      LAYER M4 ;
        RECT  115.26 85.104 115.344 85.128 ;
    END
  END x_d[41]
  PIN x_d[42]
    DIRECTION INPUT ;
    USE SIGNAL ;
    PORT
      LAYER M4 ;
        RECT  115.26 85.296 115.344 85.32 ;
    END
  END x_d[42]
  PIN x_d[43]
    DIRECTION INPUT ;
    USE SIGNAL ;
    PORT
      LAYER M4 ;
        RECT  115.26 85.44 115.344 85.464 ;
    END
  END x_d[43]
  PIN x_d[44]
    DIRECTION INPUT ;
    USE SIGNAL ;
    PORT
      LAYER M4 ;
        RECT  115.26 85.632 115.344 85.656 ;
    END
  END x_d[44]
  PIN x_d[45]
    DIRECTION INPUT ;
    USE SIGNAL ;
    PORT
      LAYER M4 ;
        RECT  115.26 85.824 115.344 85.848 ;
    END
  END x_d[45]
  PIN x_d[46]
    DIRECTION INPUT ;
    USE SIGNAL ;
    PORT
      LAYER M4 ;
        RECT  115.26 85.968 115.344 85.992 ;
    END
  END x_d[46]
  PIN x_d[47]
    DIRECTION INPUT ;
    USE SIGNAL ;
    PORT
      LAYER M4 ;
        RECT  115.26 86.16 115.344 86.184 ;
    END
  END x_d[47]
  PIN x_d[48]
    DIRECTION INPUT ;
    USE SIGNAL ;
    PORT
      LAYER M4 ;
        RECT  115.26 86.352 115.344 86.376 ;
    END
  END x_d[48]
  PIN x_d[49]
    DIRECTION INPUT ;
    USE SIGNAL ;
    PORT
      LAYER M4 ;
        RECT  115.26 86.448 115.344 86.472 ;
    END
  END x_d[49]
  PIN x_d[4]
    DIRECTION INPUT ;
    USE SIGNAL ;
    PORT
      LAYER M4 ;
        RECT  115.26 78.768 115.344 78.792 ;
    END
  END x_d[4]
  PIN x_d[50]
    DIRECTION INPUT ;
    USE SIGNAL ;
    PORT
      LAYER M4 ;
        RECT  115.26 86.64 115.344 86.664 ;
    END
  END x_d[50]
  PIN x_d[51]
    DIRECTION INPUT ;
    USE SIGNAL ;
    PORT
      LAYER M4 ;
        RECT  115.26 86.832 115.344 86.856 ;
    END
  END x_d[51]
  PIN x_d[52]
    DIRECTION INPUT ;
    USE SIGNAL ;
    PORT
      LAYER M4 ;
        RECT  115.26 86.976 115.344 87 ;
    END
  END x_d[52]
  PIN x_d[53]
    DIRECTION INPUT ;
    USE SIGNAL ;
    PORT
      LAYER M4 ;
        RECT  115.26 87.168 115.344 87.192 ;
    END
  END x_d[53]
  PIN x_d[54]
    DIRECTION INPUT ;
    USE SIGNAL ;
    PORT
      LAYER M4 ;
        RECT  115.26 87.36 115.344 87.384 ;
    END
  END x_d[54]
  PIN x_d[55]
    DIRECTION INPUT ;
    USE SIGNAL ;
    PORT
      LAYER M4 ;
        RECT  115.26 87.552 115.344 87.576 ;
    END
  END x_d[55]
  PIN x_d[56]
    DIRECTION INPUT ;
    USE SIGNAL ;
    PORT
      LAYER M4 ;
        RECT  115.26 87.696 115.344 87.72 ;
    END
  END x_d[56]
  PIN x_d[57]
    DIRECTION INPUT ;
    USE SIGNAL ;
    PORT
      LAYER M4 ;
        RECT  115.26 87.888 115.344 87.912 ;
    END
  END x_d[57]
  PIN x_d[58]
    DIRECTION INPUT ;
    USE SIGNAL ;
    PORT
      LAYER M4 ;
        RECT  115.26 88.08 115.344 88.104 ;
    END
  END x_d[58]
  PIN x_d[59]
    DIRECTION INPUT ;
    USE SIGNAL ;
    PORT
      LAYER M4 ;
        RECT  115.26 88.176 115.344 88.2 ;
    END
  END x_d[59]
  PIN x_d[5]
    DIRECTION INPUT ;
    USE SIGNAL ;
    PORT
      LAYER M4 ;
        RECT  115.26 78.912 115.344 78.936 ;
    END
  END x_d[5]
  PIN x_d[60]
    DIRECTION INPUT ;
    USE SIGNAL ;
    PORT
      LAYER M4 ;
        RECT  115.26 88.368 115.344 88.392 ;
    END
  END x_d[60]
  PIN x_d[61]
    DIRECTION INPUT ;
    USE SIGNAL ;
    PORT
      LAYER M4 ;
        RECT  115.26 88.56 115.344 88.584 ;
    END
  END x_d[61]
  PIN x_d[62]
    DIRECTION INPUT ;
    USE SIGNAL ;
    PORT
      LAYER M4 ;
        RECT  115.26 88.704 115.344 88.728 ;
    END
  END x_d[62]
  PIN x_d[63]
    DIRECTION INPUT ;
    USE SIGNAL ;
    PORT
      LAYER M4 ;
        RECT  115.26 88.896 115.344 88.92 ;
    END
  END x_d[63]
  PIN x_d[64]
    DIRECTION INPUT ;
    USE SIGNAL ;
    PORT
      LAYER M4 ;
        RECT  115.26 89.088 115.344 89.112 ;
    END
  END x_d[64]
  PIN x_d[65]
    DIRECTION INPUT ;
    USE SIGNAL ;
    PORT
      LAYER M4 ;
        RECT  115.26 89.232 115.344 89.256 ;
    END
  END x_d[65]
  PIN x_d[66]
    DIRECTION INPUT ;
    USE SIGNAL ;
    PORT
      LAYER M4 ;
        RECT  115.26 89.424 115.344 89.448 ;
    END
  END x_d[66]
  PIN x_d[67]
    DIRECTION INPUT ;
    USE SIGNAL ;
    PORT
      LAYER M4 ;
        RECT  115.26 89.568 115.344 89.592 ;
    END
  END x_d[67]
  PIN x_d[68]
    DIRECTION INPUT ;
    USE SIGNAL ;
    PORT
      LAYER M4 ;
        RECT  115.26 89.76 115.344 89.784 ;
    END
  END x_d[68]
  PIN x_d[69]
    DIRECTION INPUT ;
    USE SIGNAL ;
    PORT
      LAYER M4 ;
        RECT  115.26 89.952 115.344 89.976 ;
    END
  END x_d[69]
  PIN x_d[6]
    DIRECTION INPUT ;
    USE SIGNAL ;
    PORT
      LAYER M4 ;
        RECT  115.26 79.104 115.344 79.128 ;
    END
  END x_d[6]
  PIN x_d[70]
    DIRECTION INPUT ;
    USE SIGNAL ;
    PORT
      LAYER M4 ;
        RECT  115.26 90.096 115.344 90.12 ;
    END
  END x_d[70]
  PIN x_d[71]
    DIRECTION INPUT ;
    USE SIGNAL ;
    PORT
      LAYER M4 ;
        RECT  115.26 90.288 115.344 90.312 ;
    END
  END x_d[71]
  PIN x_d[72]
    DIRECTION INPUT ;
    USE SIGNAL ;
    PORT
      LAYER M4 ;
        RECT  115.26 90.432 115.344 90.456 ;
    END
  END x_d[72]
  PIN x_d[73]
    DIRECTION INPUT ;
    USE SIGNAL ;
    PORT
      LAYER M4 ;
        RECT  115.26 90.624 115.344 90.648 ;
    END
  END x_d[73]
  PIN x_d[74]
    DIRECTION INPUT ;
    USE SIGNAL ;
    PORT
      LAYER M4 ;
        RECT  115.26 90.816 115.344 90.84 ;
    END
  END x_d[74]
  PIN x_d[75]
    DIRECTION INPUT ;
    USE SIGNAL ;
    PORT
      LAYER M4 ;
        RECT  115.26 90.96 115.344 90.984 ;
    END
  END x_d[75]
  PIN x_d[76]
    DIRECTION INPUT ;
    USE SIGNAL ;
    PORT
      LAYER M4 ;
        RECT  115.26 91.152 115.344 91.176 ;
    END
  END x_d[76]
  PIN x_d[77]
    DIRECTION INPUT ;
    USE SIGNAL ;
    PORT
      LAYER M4 ;
        RECT  115.26 91.296 115.344 91.32 ;
    END
  END x_d[77]
  PIN x_d[78]
    DIRECTION INPUT ;
    USE SIGNAL ;
    PORT
      LAYER M4 ;
        RECT  115.26 91.488 115.344 91.512 ;
    END
  END x_d[78]
  PIN x_d[79]
    DIRECTION INPUT ;
    USE SIGNAL ;
    PORT
      LAYER M4 ;
        RECT  115.26 91.632 115.344 91.656 ;
    END
  END x_d[79]
  PIN x_d[7]
    DIRECTION INPUT ;
    USE SIGNAL ;
    PORT
      LAYER M4 ;
        RECT  115.26 79.296 115.344 79.32 ;
    END
  END x_d[7]
  PIN x_d[80]
    DIRECTION INPUT ;
    USE SIGNAL ;
    PORT
      LAYER M4 ;
        RECT  115.26 91.824 115.344 91.848 ;
    END
  END x_d[80]
  PIN x_d[81]
    DIRECTION INPUT ;
    USE SIGNAL ;
    PORT
      LAYER M4 ;
        RECT  115.26 92.016 115.344 92.04 ;
    END
  END x_d[81]
  PIN x_d[82]
    DIRECTION INPUT ;
    USE SIGNAL ;
    PORT
      LAYER M4 ;
        RECT  115.26 92.16 115.344 92.184 ;
    END
  END x_d[82]
  PIN x_d[83]
    DIRECTION INPUT ;
    USE SIGNAL ;
    PORT
      LAYER M4 ;
        RECT  115.26 92.352 115.344 92.376 ;
    END
  END x_d[83]
  PIN x_d[84]
    DIRECTION INPUT ;
    USE SIGNAL ;
    PORT
      LAYER M4 ;
        RECT  115.26 92.496 115.344 92.52 ;
    END
  END x_d[84]
  PIN x_d[85]
    DIRECTION INPUT ;
    USE SIGNAL ;
    PORT
      LAYER M4 ;
        RECT  115.26 92.688 115.344 92.712 ;
    END
  END x_d[85]
  PIN x_d[86]
    DIRECTION INPUT ;
    USE SIGNAL ;
    PORT
      LAYER M4 ;
        RECT  115.26 92.832 115.344 92.856 ;
    END
  END x_d[86]
  PIN x_d[87]
    DIRECTION INPUT ;
    USE SIGNAL ;
    PORT
      LAYER M4 ;
        RECT  115.26 93.024 115.344 93.048 ;
    END
  END x_d[87]
  PIN x_d[88]
    DIRECTION INPUT ;
    USE SIGNAL ;
    PORT
      LAYER M4 ;
        RECT  115.26 93.216 115.344 93.24 ;
    END
  END x_d[88]
  PIN x_d[89]
    DIRECTION INPUT ;
    USE SIGNAL ;
    PORT
      LAYER M4 ;
        RECT  115.26 93.36 115.344 93.384 ;
    END
  END x_d[89]
  PIN x_d[8]
    DIRECTION INPUT ;
    USE SIGNAL ;
    PORT
      LAYER M4 ;
        RECT  115.26 79.44 115.344 79.464 ;
    END
  END x_d[8]
  PIN x_d[90]
    DIRECTION INPUT ;
    USE SIGNAL ;
    PORT
      LAYER M4 ;
        RECT  115.26 93.552 115.344 93.576 ;
    END
  END x_d[90]
  PIN x_d[91]
    DIRECTION INPUT ;
    USE SIGNAL ;
    PORT
      LAYER M4 ;
        RECT  115.26 93.696 115.344 93.72 ;
    END
  END x_d[91]
  PIN x_d[92]
    DIRECTION INPUT ;
    USE SIGNAL ;
    PORT
      LAYER M4 ;
        RECT  115.26 93.888 115.344 93.912 ;
    END
  END x_d[92]
  PIN x_d[93]
    DIRECTION INPUT ;
    USE SIGNAL ;
    PORT
      LAYER M4 ;
        RECT  115.26 94.08 115.344 94.104 ;
    END
  END x_d[93]
  PIN x_d[94]
    DIRECTION INPUT ;
    USE SIGNAL ;
    PORT
      LAYER M4 ;
        RECT  115.26 94.224 115.344 94.248 ;
    END
  END x_d[94]
  PIN x_d[95]
    DIRECTION INPUT ;
    USE SIGNAL ;
    PORT
      LAYER M4 ;
        RECT  115.26 94.416 115.344 94.44 ;
    END
  END x_d[95]
  PIN x_d[96]
    DIRECTION INPUT ;
    USE SIGNAL ;
    PORT
      LAYER M4 ;
        RECT  115.26 94.608 115.344 94.632 ;
    END
  END x_d[96]
  PIN x_d[97]
    DIRECTION INPUT ;
    USE SIGNAL ;
    PORT
      LAYER M4 ;
        RECT  115.26 94.704 115.344 94.728 ;
    END
  END x_d[97]
  PIN x_d[98]
    DIRECTION INPUT ;
    USE SIGNAL ;
    PORT
      LAYER M4 ;
        RECT  115.26 94.896 115.344 94.92 ;
    END
  END x_d[98]
  PIN x_d[99]
    DIRECTION INPUT ;
    USE SIGNAL ;
    PORT
      LAYER M4 ;
        RECT  115.26 95.088 115.344 95.112 ;
    END
  END x_d[99]
  PIN x_d[9]
    DIRECTION INPUT ;
    USE SIGNAL ;
    PORT
      LAYER M4 ;
        RECT  115.26 79.632 115.344 79.656 ;
    END
  END x_d[9]
  PIN VDD
    DIRECTION INOUT ;
    USE POWER ;
    PORT
      LAYER M5 ;
        RECT  110.196 4.311 110.316 136.089 ;
        RECT  105.876 4.311 105.996 136.089 ;
        RECT  101.556 4.311 101.676 136.089 ;
        RECT  97.236 4.311 97.356 136.089 ;
        RECT  92.916 4.311 93.036 136.089 ;
        RECT  88.596 4.311 88.716 136.089 ;
        RECT  84.276 4.311 84.396 136.089 ;
        RECT  79.956 4.311 80.076 136.089 ;
        RECT  75.636 4.311 75.756 136.089 ;
        RECT  71.316 4.311 71.436 136.089 ;
        RECT  66.996 4.311 67.116 136.089 ;
        RECT  62.676 4.311 62.796 136.089 ;
        RECT  58.356 4.311 58.476 136.089 ;
        RECT  54.036 4.311 54.156 136.089 ;
        RECT  49.716 4.311 49.836 136.089 ;
        RECT  45.396 4.311 45.516 136.089 ;
        RECT  41.076 4.311 41.196 136.089 ;
        RECT  36.756 4.311 36.876 136.089 ;
        RECT  32.436 4.311 32.556 136.089 ;
        RECT  28.116 4.311 28.236 136.089 ;
        RECT  23.796 4.311 23.916 136.089 ;
        RECT  19.476 4.311 19.596 136.089 ;
        RECT  15.156 4.311 15.276 136.089 ;
        RECT  10.836 4.311 10.956 136.089 ;
        RECT  6.516 4.311 6.636 136.089 ;
    END
  END VDD
  PIN VSS
    DIRECTION INOUT ;
    USE GROUND ;
    PORT
      LAYER M5 ;
        RECT  110.004 4.297 110.124 136.103 ;
        RECT  105.684 4.297 105.804 136.103 ;
        RECT  101.364 4.297 101.484 136.103 ;
        RECT  97.044 4.297 97.164 136.103 ;
        RECT  92.724 4.297 92.844 136.103 ;
        RECT  88.404 4.297 88.524 136.103 ;
        RECT  84.084 4.297 84.204 136.103 ;
        RECT  79.764 4.297 79.884 136.103 ;
        RECT  75.444 4.297 75.564 136.103 ;
        RECT  71.124 4.297 71.244 136.103 ;
        RECT  66.804 4.297 66.924 136.103 ;
        RECT  62.484 4.297 62.604 136.103 ;
        RECT  58.164 4.297 58.284 136.103 ;
        RECT  53.844 4.297 53.964 136.103 ;
        RECT  49.524 4.297 49.644 136.103 ;
        RECT  45.204 4.297 45.324 136.103 ;
        RECT  40.884 4.297 41.004 136.103 ;
        RECT  36.564 4.297 36.684 136.103 ;
        RECT  32.244 4.297 32.364 136.103 ;
        RECT  27.924 4.297 28.044 136.103 ;
        RECT  23.604 4.297 23.724 136.103 ;
        RECT  19.284 4.297 19.404 136.103 ;
        RECT  14.964 4.297 15.084 136.103 ;
        RECT  10.644 4.297 10.764 136.103 ;
        RECT  6.324 4.297 6.444 136.103 ;
    END
  END VSS
  OBS
    LAYER RVTN ;
     RECT  4.32 4.297 115.344 140.4 ;
    LAYER RVTP ;
     RECT  4.32 4.297 115.344 140.4 ;
    LAYER M1 ;
     RECT  4.32 4.297 115.344 140.4 ;
    LAYER M2 ;
     RECT  4.32 4.297 115.344 140.4 ;
    LAYER M3 ;
     RECT  4.32 4.297 115.344 140.4 ;
    LAYER M4 ;
     RECT  4.32 4.297 115.344 140.4 ;
    LAYER M5 ;
     RECT  4.32 4.297 115.344 140.4 ;
  END
END ot_qwen_tile_lsl_rawfault_m3
END LIBRARY
